VERSION 5.7 ;
  NOWIREEXTENSIONATPIN ON ;
  DIVIDERCHAR "/" ;
  BUSBITCHARS "[]" ;
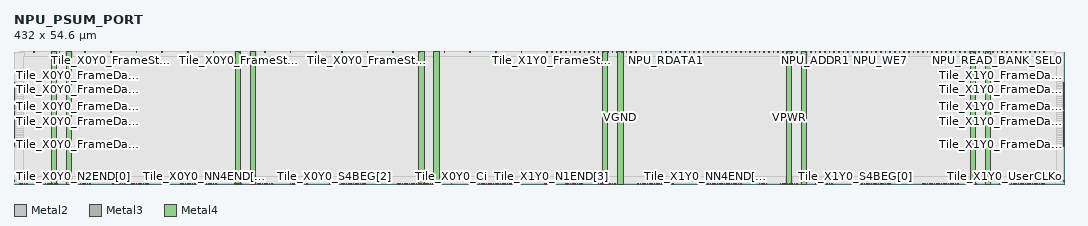
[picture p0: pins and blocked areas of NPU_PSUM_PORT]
MACRO NPU_PSUM_PORT
  CLASS BLOCK ;
  FOREIGN NPU_PSUM_PORT ;
  ORIGIN 0.000 0.000 ;
  SIZE 432.000 BY 54.600 ;
  PIN NPU_ADDR0
    DIRECTION OUTPUT ;
    USE SIGNAL ;
    ANTENNADIFFAREA 2.724000 ;
    PORT
      LAYER Metal2 ;
        RECT 327.640 54.200 328.040 54.600 ;
    END
  END NPU_ADDR0
  PIN NPU_ADDR1
    DIRECTION OUTPUT ;
    USE SIGNAL ;
    ANTENNADIFFAREA 2.724000 ;
    PORT
      LAYER Metal2 ;
        RECT 329.560 54.200 329.960 54.600 ;
    END
  END NPU_ADDR1
  PIN NPU_ADDR2
    DIRECTION OUTPUT ;
    USE SIGNAL ;
    ANTENNADIFFAREA 2.724000 ;
    PORT
      LAYER Metal2 ;
        RECT 331.480 54.200 331.880 54.600 ;
    END
  END NPU_ADDR2
  PIN NPU_ADDR3
    DIRECTION OUTPUT ;
    USE SIGNAL ;
    ANTENNADIFFAREA 2.724000 ;
    PORT
      LAYER Metal2 ;
        RECT 333.400 54.200 333.800 54.600 ;
    END
  END NPU_ADDR3
  PIN NPU_ADDR4
    DIRECTION OUTPUT ;
    USE SIGNAL ;
    ANTENNADIFFAREA 2.724000 ;
    PORT
      LAYER Metal2 ;
        RECT 335.320 54.200 335.720 54.600 ;
    END
  END NPU_ADDR4
  PIN NPU_ADDR5
    DIRECTION OUTPUT ;
    USE SIGNAL ;
    ANTENNADIFFAREA 2.724000 ;
    PORT
      LAYER Metal2 ;
        RECT 337.240 54.200 337.640 54.600 ;
    END
  END NPU_ADDR5
  PIN NPU_ADDR6
    DIRECTION OUTPUT ;
    USE SIGNAL ;
    ANTENNADIFFAREA 2.724000 ;
    PORT
      LAYER Metal2 ;
        RECT 339.160 54.200 339.560 54.600 ;
    END
  END NPU_ADDR6
  PIN NPU_ADDR7
    DIRECTION OUTPUT ;
    USE SIGNAL ;
    ANTENNADIFFAREA 2.724000 ;
    PORT
      LAYER Metal2 ;
        RECT 341.080 54.200 341.480 54.600 ;
    END
  END NPU_ADDR7
  PIN NPU_RDATA0
    DIRECTION INPUT ;
    USE SIGNAL ;
    ANTENNAGATEAREA 0.180700 ;
    ANTENNADIFFAREA 2.015400 ;
    PORT
      LAYER Metal2 ;
        RECT 266.200 54.200 266.600 54.600 ;
    END
  END NPU_RDATA0
  PIN NPU_RDATA1
    DIRECTION INPUT ;
    USE SIGNAL ;
    ANTENNAGATEAREA 0.180700 ;
    ANTENNADIFFAREA 2.015400 ;
    PORT
      LAYER Metal2 ;
        RECT 268.120 54.200 268.520 54.600 ;
    END
  END NPU_RDATA1
  PIN NPU_RDATA10
    DIRECTION INPUT ;
    USE SIGNAL ;
    ANTENNAGATEAREA 0.180700 ;
    ANTENNADIFFAREA 2.015400 ;
    PORT
      LAYER Metal2 ;
        RECT 285.400 54.200 285.800 54.600 ;
    END
  END NPU_RDATA10
  PIN NPU_RDATA11
    DIRECTION INPUT ;
    USE SIGNAL ;
    ANTENNAGATEAREA 0.180700 ;
    ANTENNADIFFAREA 2.015400 ;
    PORT
      LAYER Metal2 ;
        RECT 287.320 54.200 287.720 54.600 ;
    END
  END NPU_RDATA11
  PIN NPU_RDATA12
    DIRECTION INPUT ;
    USE SIGNAL ;
    ANTENNAGATEAREA 0.180700 ;
    ANTENNADIFFAREA 2.015400 ;
    PORT
      LAYER Metal2 ;
        RECT 289.240 54.200 289.640 54.600 ;
    END
  END NPU_RDATA12
  PIN NPU_RDATA13
    DIRECTION INPUT ;
    USE SIGNAL ;
    ANTENNAGATEAREA 0.180700 ;
    ANTENNADIFFAREA 2.015400 ;
    PORT
      LAYER Metal2 ;
        RECT 291.160 54.200 291.560 54.600 ;
    END
  END NPU_RDATA13
  PIN NPU_RDATA14
    DIRECTION INPUT ;
    USE SIGNAL ;
    ANTENNAGATEAREA 0.180700 ;
    ANTENNADIFFAREA 2.015400 ;
    PORT
      LAYER Metal2 ;
        RECT 293.080 54.200 293.480 54.600 ;
    END
  END NPU_RDATA14
  PIN NPU_RDATA15
    DIRECTION INPUT ;
    USE SIGNAL ;
    ANTENNAGATEAREA 0.180700 ;
    ANTENNADIFFAREA 2.015400 ;
    PORT
      LAYER Metal2 ;
        RECT 295.000 54.200 295.400 54.600 ;
    END
  END NPU_RDATA15
  PIN NPU_RDATA16
    DIRECTION INPUT ;
    USE SIGNAL ;
    ANTENNAGATEAREA 0.180700 ;
    ANTENNADIFFAREA 2.015400 ;
    PORT
      LAYER Metal2 ;
        RECT 296.920 54.200 297.320 54.600 ;
    END
  END NPU_RDATA16
  PIN NPU_RDATA17
    DIRECTION INPUT ;
    USE SIGNAL ;
    ANTENNAGATEAREA 0.180700 ;
    ANTENNADIFFAREA 2.015400 ;
    PORT
      LAYER Metal2 ;
        RECT 298.840 54.200 299.240 54.600 ;
    END
  END NPU_RDATA17
  PIN NPU_RDATA18
    DIRECTION INPUT ;
    USE SIGNAL ;
    ANTENNAGATEAREA 0.180700 ;
    ANTENNADIFFAREA 2.015400 ;
    PORT
      LAYER Metal2 ;
        RECT 300.760 54.200 301.160 54.600 ;
    END
  END NPU_RDATA18
  PIN NPU_RDATA19
    DIRECTION INPUT ;
    USE SIGNAL ;
    ANTENNAGATEAREA 0.180700 ;
    ANTENNADIFFAREA 2.015400 ;
    PORT
      LAYER Metal2 ;
        RECT 302.680 54.200 303.080 54.600 ;
    END
  END NPU_RDATA19
  PIN NPU_RDATA2
    DIRECTION INPUT ;
    USE SIGNAL ;
    ANTENNAGATEAREA 0.180700 ;
    ANTENNADIFFAREA 2.015400 ;
    PORT
      LAYER Metal2 ;
        RECT 270.040 54.200 270.440 54.600 ;
    END
  END NPU_RDATA2
  PIN NPU_RDATA20
    DIRECTION INPUT ;
    USE SIGNAL ;
    ANTENNAGATEAREA 0.180700 ;
    ANTENNADIFFAREA 2.015400 ;
    PORT
      LAYER Metal2 ;
        RECT 304.600 54.200 305.000 54.600 ;
    END
  END NPU_RDATA20
  PIN NPU_RDATA21
    DIRECTION INPUT ;
    USE SIGNAL ;
    ANTENNAGATEAREA 0.180700 ;
    ANTENNADIFFAREA 2.015400 ;
    PORT
      LAYER Metal2 ;
        RECT 306.520 54.200 306.920 54.600 ;
    END
  END NPU_RDATA21
  PIN NPU_RDATA22
    DIRECTION INPUT ;
    USE SIGNAL ;
    ANTENNAGATEAREA 0.180700 ;
    ANTENNADIFFAREA 2.015400 ;
    PORT
      LAYER Metal2 ;
        RECT 308.440 54.200 308.840 54.600 ;
    END
  END NPU_RDATA22
  PIN NPU_RDATA23
    DIRECTION INPUT ;
    USE SIGNAL ;
    ANTENNAGATEAREA 0.180700 ;
    ANTENNADIFFAREA 2.015400 ;
    PORT
      LAYER Metal2 ;
        RECT 310.360 54.200 310.760 54.600 ;
    END
  END NPU_RDATA23
  PIN NPU_RDATA24
    DIRECTION INPUT ;
    USE SIGNAL ;
    ANTENNAGATEAREA 0.180700 ;
    ANTENNADIFFAREA 2.015400 ;
    PORT
      LAYER Metal2 ;
        RECT 312.280 54.200 312.680 54.600 ;
    END
  END NPU_RDATA24
  PIN NPU_RDATA25
    DIRECTION INPUT ;
    USE SIGNAL ;
    ANTENNAGATEAREA 0.180700 ;
    ANTENNADIFFAREA 2.015400 ;
    PORT
      LAYER Metal2 ;
        RECT 314.200 54.200 314.600 54.600 ;
    END
  END NPU_RDATA25
  PIN NPU_RDATA26
    DIRECTION INPUT ;
    USE SIGNAL ;
    ANTENNAGATEAREA 0.180700 ;
    ANTENNADIFFAREA 2.015400 ;
    PORT
      LAYER Metal2 ;
        RECT 316.120 54.200 316.520 54.600 ;
    END
  END NPU_RDATA26
  PIN NPU_RDATA27
    DIRECTION INPUT ;
    USE SIGNAL ;
    ANTENNAGATEAREA 0.180700 ;
    ANTENNADIFFAREA 2.015400 ;
    PORT
      LAYER Metal2 ;
        RECT 318.040 54.200 318.440 54.600 ;
    END
  END NPU_RDATA27
  PIN NPU_RDATA28
    DIRECTION INPUT ;
    USE SIGNAL ;
    ANTENNAGATEAREA 0.180700 ;
    ANTENNADIFFAREA 2.015400 ;
    PORT
      LAYER Metal2 ;
        RECT 319.960 54.200 320.360 54.600 ;
    END
  END NPU_RDATA28
  PIN NPU_RDATA29
    DIRECTION INPUT ;
    USE SIGNAL ;
    ANTENNAGATEAREA 0.180700 ;
    ANTENNADIFFAREA 2.015400 ;
    PORT
      LAYER Metal2 ;
        RECT 321.880 54.200 322.280 54.600 ;
    END
  END NPU_RDATA29
  PIN NPU_RDATA3
    DIRECTION INPUT ;
    USE SIGNAL ;
    ANTENNAGATEAREA 0.180700 ;
    ANTENNADIFFAREA 2.015400 ;
    PORT
      LAYER Metal2 ;
        RECT 271.960 54.200 272.360 54.600 ;
    END
  END NPU_RDATA3
  PIN NPU_RDATA30
    DIRECTION INPUT ;
    USE SIGNAL ;
    ANTENNAGATEAREA 0.180700 ;
    ANTENNADIFFAREA 2.015400 ;
    PORT
      LAYER Metal2 ;
        RECT 323.800 54.200 324.200 54.600 ;
    END
  END NPU_RDATA30
  PIN NPU_RDATA31
    DIRECTION INPUT ;
    USE SIGNAL ;
    ANTENNAGATEAREA 0.180700 ;
    ANTENNADIFFAREA 2.015400 ;
    PORT
      LAYER Metal2 ;
        RECT 325.720 54.200 326.120 54.600 ;
    END
  END NPU_RDATA31
  PIN NPU_RDATA4
    DIRECTION INPUT ;
    USE SIGNAL ;
    ANTENNAGATEAREA 0.180700 ;
    ANTENNADIFFAREA 2.015400 ;
    PORT
      LAYER Metal2 ;
        RECT 273.880 54.200 274.280 54.600 ;
    END
  END NPU_RDATA4
  PIN NPU_RDATA5
    DIRECTION INPUT ;
    USE SIGNAL ;
    ANTENNAGATEAREA 0.180700 ;
    ANTENNADIFFAREA 2.015400 ;
    PORT
      LAYER Metal2 ;
        RECT 275.800 54.200 276.200 54.600 ;
    END
  END NPU_RDATA5
  PIN NPU_RDATA6
    DIRECTION INPUT ;
    USE SIGNAL ;
    ANTENNAGATEAREA 0.180700 ;
    ANTENNADIFFAREA 2.015400 ;
    PORT
      LAYER Metal2 ;
        RECT 277.720 54.200 278.120 54.600 ;
    END
  END NPU_RDATA6
  PIN NPU_RDATA7
    DIRECTION INPUT ;
    USE SIGNAL ;
    ANTENNAGATEAREA 0.180700 ;
    ANTENNADIFFAREA 2.015400 ;
    PORT
      LAYER Metal2 ;
        RECT 279.640 54.200 280.040 54.600 ;
    END
  END NPU_RDATA7
  PIN NPU_RDATA8
    DIRECTION INPUT ;
    USE SIGNAL ;
    ANTENNAGATEAREA 0.180700 ;
    ANTENNADIFFAREA 2.015400 ;
    PORT
      LAYER Metal2 ;
        RECT 281.560 54.200 281.960 54.600 ;
    END
  END NPU_RDATA8
  PIN NPU_RDATA9
    DIRECTION INPUT ;
    USE SIGNAL ;
    ANTENNAGATEAREA 0.180700 ;
    ANTENNADIFFAREA 2.015400 ;
    PORT
      LAYER Metal2 ;
        RECT 283.480 54.200 283.880 54.600 ;
    END
  END NPU_RDATA9
  PIN NPU_READ_BANK_SEL0
    DIRECTION OUTPUT ;
    USE SIGNAL ;
    ANTENNADIFFAREA 2.724000 ;
    PORT
      LAYER Metal2 ;
        RECT 419.800 54.200 420.200 54.600 ;
    END
  END NPU_READ_BANK_SEL0
  PIN NPU_READ_BANK_SEL1
    DIRECTION OUTPUT ;
    USE SIGNAL ;
    ANTENNADIFFAREA 2.724000 ;
    PORT
      LAYER Metal2 ;
        RECT 421.720 54.200 422.120 54.600 ;
    END
  END NPU_READ_BANK_SEL1
  PIN NPU_READ_BANK_SEL2
    DIRECTION OUTPUT ;
    USE SIGNAL ;
    ANTENNADIFFAREA 2.724000 ;
    PORT
      LAYER Metal2 ;
        RECT 423.640 54.200 424.040 54.600 ;
    END
  END NPU_READ_BANK_SEL2
  PIN NPU_WDATA0
    DIRECTION OUTPUT ;
    USE SIGNAL ;
    ANTENNADIFFAREA 2.724000 ;
    PORT
      LAYER Metal2 ;
        RECT 358.360 54.200 358.760 54.600 ;
    END
  END NPU_WDATA0
  PIN NPU_WDATA1
    DIRECTION OUTPUT ;
    USE SIGNAL ;
    ANTENNADIFFAREA 2.724000 ;
    PORT
      LAYER Metal2 ;
        RECT 360.280 54.200 360.680 54.600 ;
    END
  END NPU_WDATA1
  PIN NPU_WDATA10
    DIRECTION OUTPUT ;
    USE SIGNAL ;
    ANTENNADIFFAREA 2.724000 ;
    PORT
      LAYER Metal2 ;
        RECT 377.560 54.200 377.960 54.600 ;
    END
  END NPU_WDATA10
  PIN NPU_WDATA11
    DIRECTION OUTPUT ;
    USE SIGNAL ;
    ANTENNADIFFAREA 2.724000 ;
    PORT
      LAYER Metal2 ;
        RECT 379.480 54.200 379.880 54.600 ;
    END
  END NPU_WDATA11
  PIN NPU_WDATA12
    DIRECTION OUTPUT ;
    USE SIGNAL ;
    ANTENNADIFFAREA 2.724000 ;
    PORT
      LAYER Metal2 ;
        RECT 381.400 54.200 381.800 54.600 ;
    END
  END NPU_WDATA12
  PIN NPU_WDATA13
    DIRECTION OUTPUT ;
    USE SIGNAL ;
    ANTENNADIFFAREA 2.724000 ;
    PORT
      LAYER Metal2 ;
        RECT 383.320 54.200 383.720 54.600 ;
    END
  END NPU_WDATA13
  PIN NPU_WDATA14
    DIRECTION OUTPUT ;
    USE SIGNAL ;
    ANTENNADIFFAREA 2.724000 ;
    PORT
      LAYER Metal2 ;
        RECT 385.240 54.200 385.640 54.600 ;
    END
  END NPU_WDATA14
  PIN NPU_WDATA15
    DIRECTION OUTPUT ;
    USE SIGNAL ;
    ANTENNADIFFAREA 2.724000 ;
    PORT
      LAYER Metal2 ;
        RECT 387.160 54.200 387.560 54.600 ;
    END
  END NPU_WDATA15
  PIN NPU_WDATA16
    DIRECTION OUTPUT ;
    USE SIGNAL ;
    ANTENNADIFFAREA 2.724000 ;
    PORT
      LAYER Metal2 ;
        RECT 389.080 54.200 389.480 54.600 ;
    END
  END NPU_WDATA16
  PIN NPU_WDATA17
    DIRECTION OUTPUT ;
    USE SIGNAL ;
    ANTENNADIFFAREA 2.724000 ;
    PORT
      LAYER Metal2 ;
        RECT 391.000 54.200 391.400 54.600 ;
    END
  END NPU_WDATA17
  PIN NPU_WDATA18
    DIRECTION OUTPUT ;
    USE SIGNAL ;
    ANTENNADIFFAREA 2.724000 ;
    PORT
      LAYER Metal2 ;
        RECT 392.920 54.200 393.320 54.600 ;
    END
  END NPU_WDATA18
  PIN NPU_WDATA19
    DIRECTION OUTPUT ;
    USE SIGNAL ;
    ANTENNADIFFAREA 2.724000 ;
    PORT
      LAYER Metal2 ;
        RECT 394.840 54.200 395.240 54.600 ;
    END
  END NPU_WDATA19
  PIN NPU_WDATA2
    DIRECTION OUTPUT ;
    USE SIGNAL ;
    ANTENNADIFFAREA 2.724000 ;
    PORT
      LAYER Metal2 ;
        RECT 362.200 54.200 362.600 54.600 ;
    END
  END NPU_WDATA2
  PIN NPU_WDATA20
    DIRECTION OUTPUT ;
    USE SIGNAL ;
    ANTENNADIFFAREA 2.724000 ;
    PORT
      LAYER Metal2 ;
        RECT 396.760 54.200 397.160 54.600 ;
    END
  END NPU_WDATA20
  PIN NPU_WDATA21
    DIRECTION OUTPUT ;
    USE SIGNAL ;
    ANTENNADIFFAREA 2.724000 ;
    PORT
      LAYER Metal2 ;
        RECT 398.680 54.200 399.080 54.600 ;
    END
  END NPU_WDATA21
  PIN NPU_WDATA22
    DIRECTION OUTPUT ;
    USE SIGNAL ;
    ANTENNADIFFAREA 2.724000 ;
    PORT
      LAYER Metal2 ;
        RECT 400.600 54.200 401.000 54.600 ;
    END
  END NPU_WDATA22
  PIN NPU_WDATA23
    DIRECTION OUTPUT ;
    USE SIGNAL ;
    ANTENNADIFFAREA 2.724000 ;
    PORT
      LAYER Metal2 ;
        RECT 402.520 54.200 402.920 54.600 ;
    END
  END NPU_WDATA23
  PIN NPU_WDATA24
    DIRECTION OUTPUT ;
    USE SIGNAL ;
    ANTENNADIFFAREA 2.724000 ;
    PORT
      LAYER Metal2 ;
        RECT 404.440 54.200 404.840 54.600 ;
    END
  END NPU_WDATA24
  PIN NPU_WDATA25
    DIRECTION OUTPUT ;
    USE SIGNAL ;
    ANTENNADIFFAREA 2.724000 ;
    PORT
      LAYER Metal2 ;
        RECT 406.360 54.200 406.760 54.600 ;
    END
  END NPU_WDATA25
  PIN NPU_WDATA26
    DIRECTION OUTPUT ;
    USE SIGNAL ;
    ANTENNADIFFAREA 2.724000 ;
    PORT
      LAYER Metal2 ;
        RECT 408.280 54.200 408.680 54.600 ;
    END
  END NPU_WDATA26
  PIN NPU_WDATA27
    DIRECTION OUTPUT ;
    USE SIGNAL ;
    ANTENNADIFFAREA 2.724000 ;
    PORT
      LAYER Metal2 ;
        RECT 410.200 54.200 410.600 54.600 ;
    END
  END NPU_WDATA27
  PIN NPU_WDATA28
    DIRECTION OUTPUT ;
    USE SIGNAL ;
    ANTENNADIFFAREA 2.724000 ;
    PORT
      LAYER Metal2 ;
        RECT 412.120 54.200 412.520 54.600 ;
    END
  END NPU_WDATA28
  PIN NPU_WDATA29
    DIRECTION OUTPUT ;
    USE SIGNAL ;
    ANTENNADIFFAREA 2.724000 ;
    PORT
      LAYER Metal2 ;
        RECT 414.040 54.200 414.440 54.600 ;
    END
  END NPU_WDATA29
  PIN NPU_WDATA3
    DIRECTION OUTPUT ;
    USE SIGNAL ;
    ANTENNADIFFAREA 2.724000 ;
    PORT
      LAYER Metal2 ;
        RECT 364.120 54.200 364.520 54.600 ;
    END
  END NPU_WDATA3
  PIN NPU_WDATA30
    DIRECTION OUTPUT ;
    USE SIGNAL ;
    ANTENNADIFFAREA 2.724000 ;
    PORT
      LAYER Metal2 ;
        RECT 415.960 54.200 416.360 54.600 ;
    END
  END NPU_WDATA30
  PIN NPU_WDATA31
    DIRECTION OUTPUT ;
    USE SIGNAL ;
    ANTENNADIFFAREA 2.724000 ;
    PORT
      LAYER Metal2 ;
        RECT 417.880 54.200 418.280 54.600 ;
    END
  END NPU_WDATA31
  PIN NPU_WDATA4
    DIRECTION OUTPUT ;
    USE SIGNAL ;
    ANTENNADIFFAREA 2.724000 ;
    PORT
      LAYER Metal2 ;
        RECT 366.040 54.200 366.440 54.600 ;
    END
  END NPU_WDATA4
  PIN NPU_WDATA5
    DIRECTION OUTPUT ;
    USE SIGNAL ;
    ANTENNADIFFAREA 2.724000 ;
    PORT
      LAYER Metal2 ;
        RECT 367.960 54.200 368.360 54.600 ;
    END
  END NPU_WDATA5
  PIN NPU_WDATA6
    DIRECTION OUTPUT ;
    USE SIGNAL ;
    ANTENNADIFFAREA 2.724000 ;
    PORT
      LAYER Metal2 ;
        RECT 369.880 54.200 370.280 54.600 ;
    END
  END NPU_WDATA6
  PIN NPU_WDATA7
    DIRECTION OUTPUT ;
    USE SIGNAL ;
    ANTENNADIFFAREA 2.724000 ;
    PORT
      LAYER Metal2 ;
        RECT 371.800 54.200 372.200 54.600 ;
    END
  END NPU_WDATA7
  PIN NPU_WDATA8
    DIRECTION OUTPUT ;
    USE SIGNAL ;
    ANTENNADIFFAREA 2.724000 ;
    PORT
      LAYER Metal2 ;
        RECT 373.720 54.200 374.120 54.600 ;
    END
  END NPU_WDATA8
  PIN NPU_WDATA9
    DIRECTION OUTPUT ;
    USE SIGNAL ;
    ANTENNADIFFAREA 2.724000 ;
    PORT
      LAYER Metal2 ;
        RECT 375.640 54.200 376.040 54.600 ;
    END
  END NPU_WDATA9
  PIN NPU_WE0
    DIRECTION OUTPUT ;
    USE SIGNAL ;
    ANTENNADIFFAREA 2.724000 ;
    PORT
      LAYER Metal2 ;
        RECT 343.000 54.200 343.400 54.600 ;
    END
  END NPU_WE0
  PIN NPU_WE1
    DIRECTION OUTPUT ;
    USE SIGNAL ;
    ANTENNADIFFAREA 2.724000 ;
    PORT
      LAYER Metal2 ;
        RECT 344.920 54.200 345.320 54.600 ;
    END
  END NPU_WE1
  PIN NPU_WE2
    DIRECTION OUTPUT ;
    USE SIGNAL ;
    ANTENNADIFFAREA 2.724000 ;
    PORT
      LAYER Metal2 ;
        RECT 346.840 54.200 347.240 54.600 ;
    END
  END NPU_WE2
  PIN NPU_WE3
    DIRECTION OUTPUT ;
    USE SIGNAL ;
    ANTENNADIFFAREA 2.724000 ;
    PORT
      LAYER Metal2 ;
        RECT 348.760 54.200 349.160 54.600 ;
    END
  END NPU_WE3
  PIN NPU_WE4
    DIRECTION OUTPUT ;
    USE SIGNAL ;
    ANTENNADIFFAREA 2.724000 ;
    PORT
      LAYER Metal2 ;
        RECT 350.680 54.200 351.080 54.600 ;
    END
  END NPU_WE4
  PIN NPU_WE5
    DIRECTION OUTPUT ;
    USE SIGNAL ;
    ANTENNADIFFAREA 2.724000 ;
    PORT
      LAYER Metal2 ;
        RECT 352.600 54.200 353.000 54.600 ;
    END
  END NPU_WE5
  PIN NPU_WE6
    DIRECTION OUTPUT ;
    USE SIGNAL ;
    ANTENNADIFFAREA 2.724000 ;
    PORT
      LAYER Metal2 ;
        RECT 354.520 54.200 354.920 54.600 ;
    END
  END NPU_WE6
  PIN NPU_WE7
    DIRECTION OUTPUT ;
    USE SIGNAL ;
    ANTENNADIFFAREA 2.724000 ;
    PORT
      LAYER Metal2 ;
        RECT 356.440 54.200 356.840 54.600 ;
    END
  END NPU_WE7
  PIN Tile_X0Y0_Ci
    DIRECTION INPUT ;
    USE SIGNAL ;
    PORT
      LAYER Metal2 ;
        RECT 179.800 0.000 180.200 0.400 ;
    END
  END Tile_X0Y0_Ci
  PIN Tile_X0Y0_FrameData[0]
    DIRECTION INPUT ;
    USE SIGNAL ;
    ANTENNAGATEAREA 0.180700 ;
    ANTENNADIFFAREA 2.015400 ;
    PORT
      LAYER Metal3 ;
        RECT 0.000 15.340 0.400 15.740 ;
    END
  END Tile_X0Y0_FrameData[0]
  PIN Tile_X0Y0_FrameData[10]
    DIRECTION INPUT ;
    USE SIGNAL ;
    ANTENNAGATEAREA 0.180700 ;
    ANTENNADIFFAREA 2.015400 ;
    PORT
      LAYER Metal3 ;
        RECT 0.000 23.740 0.400 24.140 ;
    END
  END Tile_X0Y0_FrameData[10]
  PIN Tile_X0Y0_FrameData[11]
    DIRECTION INPUT ;
    USE SIGNAL ;
    ANTENNAGATEAREA 0.180700 ;
    ANTENNADIFFAREA 2.015400 ;
    PORT
      LAYER Metal3 ;
        RECT 0.000 24.580 0.400 24.980 ;
    END
  END Tile_X0Y0_FrameData[11]
  PIN Tile_X0Y0_FrameData[12]
    DIRECTION INPUT ;
    USE SIGNAL ;
    ANTENNAGATEAREA 0.180700 ;
    ANTENNADIFFAREA 2.015400 ;
    PORT
      LAYER Metal3 ;
        RECT 0.000 25.420 0.400 25.820 ;
    END
  END Tile_X0Y0_FrameData[12]
  PIN Tile_X0Y0_FrameData[13]
    DIRECTION INPUT ;
    USE SIGNAL ;
    ANTENNAGATEAREA 0.180700 ;
    ANTENNADIFFAREA 2.015400 ;
    PORT
      LAYER Metal3 ;
        RECT 0.000 26.260 0.400 26.660 ;
    END
  END Tile_X0Y0_FrameData[13]
  PIN Tile_X0Y0_FrameData[14]
    DIRECTION INPUT ;
    USE SIGNAL ;
    ANTENNAGATEAREA 0.180700 ;
    ANTENNADIFFAREA 2.015400 ;
    PORT
      LAYER Metal3 ;
        RECT 0.000 27.100 0.400 27.500 ;
    END
  END Tile_X0Y0_FrameData[14]
  PIN Tile_X0Y0_FrameData[15]
    DIRECTION INPUT ;
    USE SIGNAL ;
    ANTENNAGATEAREA 0.180700 ;
    ANTENNADIFFAREA 2.015400 ;
    PORT
      LAYER Metal3 ;
        RECT 0.000 27.940 0.400 28.340 ;
    END
  END Tile_X0Y0_FrameData[15]
  PIN Tile_X0Y0_FrameData[16]
    DIRECTION INPUT ;
    USE SIGNAL ;
    ANTENNAGATEAREA 0.180700 ;
    ANTENNADIFFAREA 2.015400 ;
    PORT
      LAYER Metal3 ;
        RECT 0.000 28.780 0.400 29.180 ;
    END
  END Tile_X0Y0_FrameData[16]
  PIN Tile_X0Y0_FrameData[17]
    DIRECTION INPUT ;
    USE SIGNAL ;
    ANTENNAGATEAREA 0.180700 ;
    ANTENNADIFFAREA 2.015400 ;
    PORT
      LAYER Metal3 ;
        RECT 0.000 29.620 0.400 30.020 ;
    END
  END Tile_X0Y0_FrameData[17]
  PIN Tile_X0Y0_FrameData[18]
    DIRECTION INPUT ;
    USE SIGNAL ;
    ANTENNAGATEAREA 0.180700 ;
    ANTENNADIFFAREA 2.015400 ;
    PORT
      LAYER Metal3 ;
        RECT 0.000 30.460 0.400 30.860 ;
    END
  END Tile_X0Y0_FrameData[18]
  PIN Tile_X0Y0_FrameData[19]
    DIRECTION INPUT ;
    USE SIGNAL ;
    ANTENNAGATEAREA 0.180700 ;
    ANTENNADIFFAREA 2.015400 ;
    PORT
      LAYER Metal3 ;
        RECT 0.000 31.300 0.400 31.700 ;
    END
  END Tile_X0Y0_FrameData[19]
  PIN Tile_X0Y0_FrameData[1]
    DIRECTION INPUT ;
    USE SIGNAL ;
    ANTENNAGATEAREA 0.180700 ;
    ANTENNADIFFAREA 2.015400 ;
    PORT
      LAYER Metal3 ;
        RECT 0.000 16.180 0.400 16.580 ;
    END
  END Tile_X0Y0_FrameData[1]
  PIN Tile_X0Y0_FrameData[20]
    DIRECTION INPUT ;
    USE SIGNAL ;
    ANTENNAGATEAREA 0.180700 ;
    ANTENNADIFFAREA 2.015400 ;
    PORT
      LAYER Metal3 ;
        RECT 0.000 32.140 0.400 32.540 ;
    END
  END Tile_X0Y0_FrameData[20]
  PIN Tile_X0Y0_FrameData[21]
    DIRECTION INPUT ;
    USE SIGNAL ;
    ANTENNAGATEAREA 0.180700 ;
    ANTENNADIFFAREA 2.015400 ;
    PORT
      LAYER Metal3 ;
        RECT 0.000 32.980 0.400 33.380 ;
    END
  END Tile_X0Y0_FrameData[21]
  PIN Tile_X0Y0_FrameData[22]
    DIRECTION INPUT ;
    USE SIGNAL ;
    ANTENNAGATEAREA 0.180700 ;
    ANTENNADIFFAREA 2.015400 ;
    PORT
      LAYER Metal3 ;
        RECT 0.000 33.820 0.400 34.220 ;
    END
  END Tile_X0Y0_FrameData[22]
  PIN Tile_X0Y0_FrameData[23]
    DIRECTION INPUT ;
    USE SIGNAL ;
    ANTENNAGATEAREA 0.180700 ;
    ANTENNADIFFAREA 2.015400 ;
    PORT
      LAYER Metal3 ;
        RECT 0.000 34.660 0.400 35.060 ;
    END
  END Tile_X0Y0_FrameData[23]
  PIN Tile_X0Y0_FrameData[24]
    DIRECTION INPUT ;
    USE SIGNAL ;
    ANTENNAGATEAREA 0.180700 ;
    ANTENNADIFFAREA 2.015400 ;
    PORT
      LAYER Metal3 ;
        RECT 0.000 35.500 0.400 35.900 ;
    END
  END Tile_X0Y0_FrameData[24]
  PIN Tile_X0Y0_FrameData[25]
    DIRECTION INPUT ;
    USE SIGNAL ;
    ANTENNAGATEAREA 0.180700 ;
    ANTENNADIFFAREA 2.015400 ;
    PORT
      LAYER Metal3 ;
        RECT 0.000 36.340 0.400 36.740 ;
    END
  END Tile_X0Y0_FrameData[25]
  PIN Tile_X0Y0_FrameData[26]
    DIRECTION INPUT ;
    USE SIGNAL ;
    ANTENNAGATEAREA 0.180700 ;
    ANTENNADIFFAREA 2.015400 ;
    PORT
      LAYER Metal3 ;
        RECT 0.000 37.180 0.400 37.580 ;
    END
  END Tile_X0Y0_FrameData[26]
  PIN Tile_X0Y0_FrameData[27]
    DIRECTION INPUT ;
    USE SIGNAL ;
    ANTENNAGATEAREA 0.180700 ;
    ANTENNADIFFAREA 2.015400 ;
    PORT
      LAYER Metal3 ;
        RECT 0.000 38.020 0.400 38.420 ;
    END
  END Tile_X0Y0_FrameData[27]
  PIN Tile_X0Y0_FrameData[28]
    DIRECTION INPUT ;
    USE SIGNAL ;
    ANTENNAGATEAREA 0.180700 ;
    ANTENNADIFFAREA 2.015400 ;
    PORT
      LAYER Metal3 ;
        RECT 0.000 38.860 0.400 39.260 ;
    END
  END Tile_X0Y0_FrameData[28]
  PIN Tile_X0Y0_FrameData[29]
    DIRECTION INPUT ;
    USE SIGNAL ;
    ANTENNAGATEAREA 0.180700 ;
    ANTENNADIFFAREA 2.015400 ;
    PORT
      LAYER Metal3 ;
        RECT 0.000 39.700 0.400 40.100 ;
    END
  END Tile_X0Y0_FrameData[29]
  PIN Tile_X0Y0_FrameData[2]
    DIRECTION INPUT ;
    USE SIGNAL ;
    ANTENNAGATEAREA 0.180700 ;
    ANTENNADIFFAREA 2.015400 ;
    PORT
      LAYER Metal3 ;
        RECT 0.000 17.020 0.400 17.420 ;
    END
  END Tile_X0Y0_FrameData[2]
  PIN Tile_X0Y0_FrameData[30]
    DIRECTION INPUT ;
    USE SIGNAL ;
    ANTENNAGATEAREA 0.180700 ;
    ANTENNADIFFAREA 2.015400 ;
    PORT
      LAYER Metal3 ;
        RECT 0.000 40.540 0.400 40.940 ;
    END
  END Tile_X0Y0_FrameData[30]
  PIN Tile_X0Y0_FrameData[31]
    DIRECTION INPUT ;
    USE SIGNAL ;
    ANTENNAGATEAREA 0.180700 ;
    ANTENNADIFFAREA 2.015400 ;
    PORT
      LAYER Metal3 ;
        RECT 0.000 41.380 0.400 41.780 ;
    END
  END Tile_X0Y0_FrameData[31]
  PIN Tile_X0Y0_FrameData[3]
    DIRECTION INPUT ;
    USE SIGNAL ;
    ANTENNAGATEAREA 0.180700 ;
    ANTENNADIFFAREA 2.015400 ;
    PORT
      LAYER Metal3 ;
        RECT 0.000 17.860 0.400 18.260 ;
    END
  END Tile_X0Y0_FrameData[3]
  PIN Tile_X0Y0_FrameData[4]
    DIRECTION INPUT ;
    USE SIGNAL ;
    ANTENNAGATEAREA 0.180700 ;
    ANTENNADIFFAREA 2.015400 ;
    PORT
      LAYER Metal3 ;
        RECT 0.000 18.700 0.400 19.100 ;
    END
  END Tile_X0Y0_FrameData[4]
  PIN Tile_X0Y0_FrameData[5]
    DIRECTION INPUT ;
    USE SIGNAL ;
    ANTENNAGATEAREA 0.180700 ;
    ANTENNADIFFAREA 2.015400 ;
    PORT
      LAYER Metal3 ;
        RECT 0.000 19.540 0.400 19.940 ;
    END
  END Tile_X0Y0_FrameData[5]
  PIN Tile_X0Y0_FrameData[6]
    DIRECTION INPUT ;
    USE SIGNAL ;
    ANTENNAGATEAREA 0.180700 ;
    ANTENNADIFFAREA 2.015400 ;
    PORT
      LAYER Metal3 ;
        RECT 0.000 20.380 0.400 20.780 ;
    END
  END Tile_X0Y0_FrameData[6]
  PIN Tile_X0Y0_FrameData[7]
    DIRECTION INPUT ;
    USE SIGNAL ;
    ANTENNAGATEAREA 0.180700 ;
    ANTENNADIFFAREA 2.015400 ;
    PORT
      LAYER Metal3 ;
        RECT 0.000 21.220 0.400 21.620 ;
    END
  END Tile_X0Y0_FrameData[7]
  PIN Tile_X0Y0_FrameData[8]
    DIRECTION INPUT ;
    USE SIGNAL ;
    ANTENNAGATEAREA 0.180700 ;
    ANTENNADIFFAREA 2.015400 ;
    PORT
      LAYER Metal3 ;
        RECT 0.000 22.060 0.400 22.460 ;
    END
  END Tile_X0Y0_FrameData[8]
  PIN Tile_X0Y0_FrameData[9]
    DIRECTION INPUT ;
    USE SIGNAL ;
    ANTENNAGATEAREA 0.180700 ;
    ANTENNADIFFAREA 2.015400 ;
    PORT
      LAYER Metal3 ;
        RECT 0.000 22.900 0.400 23.300 ;
    END
  END Tile_X0Y0_FrameData[9]
  PIN Tile_X0Y0_FrameStrobe[0]
    DIRECTION INPUT ;
    USE SIGNAL ;
    ANTENNAGATEAREA 0.180700 ;
    ANTENNADIFFAREA 2.015400 ;
    PORT
      LAYER Metal2 ;
        RECT 189.400 0.000 189.800 0.400 ;
    END
  END Tile_X0Y0_FrameStrobe[0]
  PIN Tile_X0Y0_FrameStrobe[10]
    DIRECTION INPUT ;
    USE SIGNAL ;
    ANTENNAGATEAREA 0.180700 ;
    ANTENNADIFFAREA 2.015400 ;
    PORT
      LAYER Metal2 ;
        RECT 199.000 0.000 199.400 0.400 ;
    END
  END Tile_X0Y0_FrameStrobe[10]
  PIN Tile_X0Y0_FrameStrobe[11]
    DIRECTION INPUT ;
    USE SIGNAL ;
    ANTENNAGATEAREA 0.180700 ;
    ANTENNADIFFAREA 2.015400 ;
    PORT
      LAYER Metal2 ;
        RECT 199.960 0.000 200.360 0.400 ;
    END
  END Tile_X0Y0_FrameStrobe[11]
  PIN Tile_X0Y0_FrameStrobe[12]
    DIRECTION INPUT ;
    USE SIGNAL ;
    ANTENNAGATEAREA 0.180700 ;
    ANTENNADIFFAREA 2.015400 ;
    PORT
      LAYER Metal2 ;
        RECT 200.920 0.000 201.320 0.400 ;
    END
  END Tile_X0Y0_FrameStrobe[12]
  PIN Tile_X0Y0_FrameStrobe[13]
    DIRECTION INPUT ;
    USE SIGNAL ;
    ANTENNAGATEAREA 0.180700 ;
    ANTENNADIFFAREA 2.015400 ;
    PORT
      LAYER Metal2 ;
        RECT 201.880 0.000 202.280 0.400 ;
    END
  END Tile_X0Y0_FrameStrobe[13]
  PIN Tile_X0Y0_FrameStrobe[14]
    DIRECTION INPUT ;
    USE SIGNAL ;
    ANTENNAGATEAREA 0.180700 ;
    ANTENNADIFFAREA 2.015400 ;
    PORT
      LAYER Metal2 ;
        RECT 202.840 0.000 203.240 0.400 ;
    END
  END Tile_X0Y0_FrameStrobe[14]
  PIN Tile_X0Y0_FrameStrobe[15]
    DIRECTION INPUT ;
    USE SIGNAL ;
    ANTENNAGATEAREA 0.180700 ;
    ANTENNADIFFAREA 2.015400 ;
    PORT
      LAYER Metal2 ;
        RECT 203.800 0.000 204.200 0.400 ;
    END
  END Tile_X0Y0_FrameStrobe[15]
  PIN Tile_X0Y0_FrameStrobe[16]
    DIRECTION INPUT ;
    USE SIGNAL ;
    ANTENNAGATEAREA 0.180700 ;
    ANTENNADIFFAREA 2.015400 ;
    PORT
      LAYER Metal2 ;
        RECT 204.760 0.000 205.160 0.400 ;
    END
  END Tile_X0Y0_FrameStrobe[16]
  PIN Tile_X0Y0_FrameStrobe[17]
    DIRECTION INPUT ;
    USE SIGNAL ;
    ANTENNAGATEAREA 0.180700 ;
    ANTENNADIFFAREA 2.015400 ;
    PORT
      LAYER Metal2 ;
        RECT 205.720 0.000 206.120 0.400 ;
    END
  END Tile_X0Y0_FrameStrobe[17]
  PIN Tile_X0Y0_FrameStrobe[18]
    DIRECTION INPUT ;
    USE SIGNAL ;
    ANTENNAGATEAREA 0.180700 ;
    ANTENNADIFFAREA 2.015400 ;
    PORT
      LAYER Metal2 ;
        RECT 206.680 0.000 207.080 0.400 ;
    END
  END Tile_X0Y0_FrameStrobe[18]
  PIN Tile_X0Y0_FrameStrobe[19]
    DIRECTION INPUT ;
    USE SIGNAL ;
    ANTENNAGATEAREA 0.180700 ;
    ANTENNADIFFAREA 2.015400 ;
    PORT
      LAYER Metal2 ;
        RECT 207.640 0.000 208.040 0.400 ;
    END
  END Tile_X0Y0_FrameStrobe[19]
  PIN Tile_X0Y0_FrameStrobe[1]
    DIRECTION INPUT ;
    USE SIGNAL ;
    ANTENNAGATEAREA 0.180700 ;
    ANTENNADIFFAREA 2.015400 ;
    PORT
      LAYER Metal2 ;
        RECT 190.360 0.000 190.760 0.400 ;
    END
  END Tile_X0Y0_FrameStrobe[1]
  PIN Tile_X0Y0_FrameStrobe[2]
    DIRECTION INPUT ;
    USE SIGNAL ;
    ANTENNAGATEAREA 0.180700 ;
    ANTENNADIFFAREA 2.015400 ;
    PORT
      LAYER Metal2 ;
        RECT 191.320 0.000 191.720 0.400 ;
    END
  END Tile_X0Y0_FrameStrobe[2]
  PIN Tile_X0Y0_FrameStrobe[3]
    DIRECTION INPUT ;
    USE SIGNAL ;
    ANTENNAGATEAREA 0.180700 ;
    ANTENNADIFFAREA 2.015400 ;
    PORT
      LAYER Metal2 ;
        RECT 192.280 0.000 192.680 0.400 ;
    END
  END Tile_X0Y0_FrameStrobe[3]
  PIN Tile_X0Y0_FrameStrobe[4]
    DIRECTION INPUT ;
    USE SIGNAL ;
    ANTENNAGATEAREA 0.180700 ;
    ANTENNADIFFAREA 2.015400 ;
    PORT
      LAYER Metal2 ;
        RECT 193.240 0.000 193.640 0.400 ;
    END
  END Tile_X0Y0_FrameStrobe[4]
  PIN Tile_X0Y0_FrameStrobe[5]
    DIRECTION INPUT ;
    USE SIGNAL ;
    ANTENNAGATEAREA 0.180700 ;
    ANTENNADIFFAREA 2.015400 ;
    PORT
      LAYER Metal2 ;
        RECT 194.200 0.000 194.600 0.400 ;
    END
  END Tile_X0Y0_FrameStrobe[5]
  PIN Tile_X0Y0_FrameStrobe[6]
    DIRECTION INPUT ;
    USE SIGNAL ;
    ANTENNAGATEAREA 0.180700 ;
    ANTENNADIFFAREA 2.015400 ;
    PORT
      LAYER Metal2 ;
        RECT 195.160 0.000 195.560 0.400 ;
    END
  END Tile_X0Y0_FrameStrobe[6]
  PIN Tile_X0Y0_FrameStrobe[7]
    DIRECTION INPUT ;
    USE SIGNAL ;
    ANTENNAGATEAREA 0.180700 ;
    ANTENNADIFFAREA 2.015400 ;
    PORT
      LAYER Metal2 ;
        RECT 196.120 0.000 196.520 0.400 ;
    END
  END Tile_X0Y0_FrameStrobe[7]
  PIN Tile_X0Y0_FrameStrobe[8]
    DIRECTION INPUT ;
    USE SIGNAL ;
    ANTENNAGATEAREA 0.180700 ;
    ANTENNADIFFAREA 2.015400 ;
    PORT
      LAYER Metal2 ;
        RECT 197.080 0.000 197.480 0.400 ;
    END
  END Tile_X0Y0_FrameStrobe[8]
  PIN Tile_X0Y0_FrameStrobe[9]
    DIRECTION INPUT ;
    USE SIGNAL ;
    ANTENNAGATEAREA 0.180700 ;
    ANTENNADIFFAREA 2.015400 ;
    PORT
      LAYER Metal2 ;
        RECT 198.040 0.000 198.440 0.400 ;
    END
  END Tile_X0Y0_FrameStrobe[9]
  PIN Tile_X0Y0_FrameStrobe_O[0]
    DIRECTION OUTPUT ;
    USE SIGNAL ;
    ANTENNADIFFAREA 2.724000 ;
    PORT
      LAYER Metal2 ;
        RECT 7.960 54.200 8.360 54.600 ;
    END
  END Tile_X0Y0_FrameStrobe_O[0]
  PIN Tile_X0Y0_FrameStrobe_O[10]
    DIRECTION OUTPUT ;
    USE SIGNAL ;
    ANTENNADIFFAREA 2.724000 ;
    PORT
      LAYER Metal2 ;
        RECT 113.560 54.200 113.960 54.600 ;
    END
  END Tile_X0Y0_FrameStrobe_O[10]
  PIN Tile_X0Y0_FrameStrobe_O[11]
    DIRECTION OUTPUT ;
    USE SIGNAL ;
    ANTENNADIFFAREA 2.724000 ;
    PORT
      LAYER Metal2 ;
        RECT 124.120 54.200 124.520 54.600 ;
    END
  END Tile_X0Y0_FrameStrobe_O[11]
  PIN Tile_X0Y0_FrameStrobe_O[12]
    DIRECTION OUTPUT ;
    USE SIGNAL ;
    ANTENNADIFFAREA 2.724000 ;
    PORT
      LAYER Metal2 ;
        RECT 134.680 54.200 135.080 54.600 ;
    END
  END Tile_X0Y0_FrameStrobe_O[12]
  PIN Tile_X0Y0_FrameStrobe_O[13]
    DIRECTION OUTPUT ;
    USE SIGNAL ;
    ANTENNADIFFAREA 2.724000 ;
    PORT
      LAYER Metal2 ;
        RECT 145.240 54.200 145.640 54.600 ;
    END
  END Tile_X0Y0_FrameStrobe_O[13]
  PIN Tile_X0Y0_FrameStrobe_O[14]
    DIRECTION OUTPUT ;
    USE SIGNAL ;
    ANTENNADIFFAREA 2.724000 ;
    PORT
      LAYER Metal2 ;
        RECT 155.800 54.200 156.200 54.600 ;
    END
  END Tile_X0Y0_FrameStrobe_O[14]
  PIN Tile_X0Y0_FrameStrobe_O[15]
    DIRECTION OUTPUT ;
    USE SIGNAL ;
    ANTENNADIFFAREA 2.724000 ;
    PORT
      LAYER Metal2 ;
        RECT 166.360 54.200 166.760 54.600 ;
    END
  END Tile_X0Y0_FrameStrobe_O[15]
  PIN Tile_X0Y0_FrameStrobe_O[16]
    DIRECTION OUTPUT ;
    USE SIGNAL ;
    ANTENNADIFFAREA 2.724000 ;
    PORT
      LAYER Metal2 ;
        RECT 176.920 54.200 177.320 54.600 ;
    END
  END Tile_X0Y0_FrameStrobe_O[16]
  PIN Tile_X0Y0_FrameStrobe_O[17]
    DIRECTION OUTPUT ;
    USE SIGNAL ;
    ANTENNADIFFAREA 2.724000 ;
    PORT
      LAYER Metal2 ;
        RECT 187.480 54.200 187.880 54.600 ;
    END
  END Tile_X0Y0_FrameStrobe_O[17]
  PIN Tile_X0Y0_FrameStrobe_O[18]
    DIRECTION OUTPUT ;
    USE SIGNAL ;
    ANTENNADIFFAREA 2.724000 ;
    PORT
      LAYER Metal2 ;
        RECT 198.040 54.200 198.440 54.600 ;
    END
  END Tile_X0Y0_FrameStrobe_O[18]
  PIN Tile_X0Y0_FrameStrobe_O[19]
    DIRECTION OUTPUT ;
    USE SIGNAL ;
    ANTENNADIFFAREA 2.724000 ;
    PORT
      LAYER Metal2 ;
        RECT 208.600 54.200 209.000 54.600 ;
    END
  END Tile_X0Y0_FrameStrobe_O[19]
  PIN Tile_X0Y0_FrameStrobe_O[1]
    DIRECTION OUTPUT ;
    USE SIGNAL ;
    ANTENNADIFFAREA 2.724000 ;
    PORT
      LAYER Metal2 ;
        RECT 18.520 54.200 18.920 54.600 ;
    END
  END Tile_X0Y0_FrameStrobe_O[1]
  PIN Tile_X0Y0_FrameStrobe_O[2]
    DIRECTION OUTPUT ;
    USE SIGNAL ;
    ANTENNADIFFAREA 2.724000 ;
    PORT
      LAYER Metal2 ;
        RECT 29.080 54.200 29.480 54.600 ;
    END
  END Tile_X0Y0_FrameStrobe_O[2]
  PIN Tile_X0Y0_FrameStrobe_O[3]
    DIRECTION OUTPUT ;
    USE SIGNAL ;
    ANTENNADIFFAREA 2.724000 ;
    PORT
      LAYER Metal2 ;
        RECT 39.640 54.200 40.040 54.600 ;
    END
  END Tile_X0Y0_FrameStrobe_O[3]
  PIN Tile_X0Y0_FrameStrobe_O[4]
    DIRECTION OUTPUT ;
    USE SIGNAL ;
    ANTENNADIFFAREA 2.724000 ;
    PORT
      LAYER Metal2 ;
        RECT 50.200 54.200 50.600 54.600 ;
    END
  END Tile_X0Y0_FrameStrobe_O[4]
  PIN Tile_X0Y0_FrameStrobe_O[5]
    DIRECTION OUTPUT ;
    USE SIGNAL ;
    ANTENNADIFFAREA 2.724000 ;
    PORT
      LAYER Metal2 ;
        RECT 60.760 54.200 61.160 54.600 ;
    END
  END Tile_X0Y0_FrameStrobe_O[5]
  PIN Tile_X0Y0_FrameStrobe_O[6]
    DIRECTION OUTPUT ;
    USE SIGNAL ;
    ANTENNADIFFAREA 2.724000 ;
    PORT
      LAYER Metal2 ;
        RECT 71.320 54.200 71.720 54.600 ;
    END
  END Tile_X0Y0_FrameStrobe_O[6]
  PIN Tile_X0Y0_FrameStrobe_O[7]
    DIRECTION OUTPUT ;
    USE SIGNAL ;
    ANTENNADIFFAREA 2.724000 ;
    PORT
      LAYER Metal2 ;
        RECT 81.880 54.200 82.280 54.600 ;
    END
  END Tile_X0Y0_FrameStrobe_O[7]
  PIN Tile_X0Y0_FrameStrobe_O[8]
    DIRECTION OUTPUT ;
    USE SIGNAL ;
    ANTENNADIFFAREA 2.724000 ;
    PORT
      LAYER Metal2 ;
        RECT 92.440 54.200 92.840 54.600 ;
    END
  END Tile_X0Y0_FrameStrobe_O[8]
  PIN Tile_X0Y0_FrameStrobe_O[9]
    DIRECTION OUTPUT ;
    USE SIGNAL ;
    ANTENNADIFFAREA 2.724000 ;
    PORT
      LAYER Metal2 ;
        RECT 103.000 54.200 103.400 54.600 ;
    END
  END Tile_X0Y0_FrameStrobe_O[9]
  PIN Tile_X0Y0_N1END[0]
    DIRECTION INPUT ;
    USE SIGNAL ;
    ANTENNAGATEAREA 0.180700 ;
    ANTENNADIFFAREA 2.015400 ;
    PORT
      LAYER Metal2 ;
        RECT 2.200 0.000 2.600 0.400 ;
    END
  END Tile_X0Y0_N1END[0]
  PIN Tile_X0Y0_N1END[1]
    DIRECTION INPUT ;
    USE SIGNAL ;
    ANTENNAGATEAREA 0.180700 ;
    ANTENNADIFFAREA 2.015400 ;
    PORT
      LAYER Metal2 ;
        RECT 3.160 0.000 3.560 0.400 ;
    END
  END Tile_X0Y0_N1END[1]
  PIN Tile_X0Y0_N1END[2]
    DIRECTION INPUT ;
    USE SIGNAL ;
    ANTENNAGATEAREA 0.180700 ;
    ANTENNADIFFAREA 2.015400 ;
    PORT
      LAYER Metal2 ;
        RECT 4.120 0.000 4.520 0.400 ;
    END
  END Tile_X0Y0_N1END[2]
  PIN Tile_X0Y0_N1END[3]
    DIRECTION INPUT ;
    USE SIGNAL ;
    ANTENNAGATEAREA 0.180700 ;
    ANTENNADIFFAREA 2.015400 ;
    PORT
      LAYER Metal2 ;
        RECT 5.080 0.000 5.480 0.400 ;
    END
  END Tile_X0Y0_N1END[3]
  PIN Tile_X0Y0_N2END[0]
    DIRECTION INPUT ;
    USE SIGNAL ;
    ANTENNAGATEAREA 0.180700 ;
    ANTENNADIFFAREA 2.015400 ;
    PORT
      LAYER Metal2 ;
        RECT 24.280 0.000 24.680 0.400 ;
    END
  END Tile_X0Y0_N2END[0]
  PIN Tile_X0Y0_N2END[1]
    DIRECTION INPUT ;
    USE SIGNAL ;
    ANTENNAGATEAREA 0.180700 ;
    ANTENNADIFFAREA 2.015400 ;
    PORT
      LAYER Metal2 ;
        RECT 25.240 0.000 25.640 0.400 ;
    END
  END Tile_X0Y0_N2END[1]
  PIN Tile_X0Y0_N2END[2]
    DIRECTION INPUT ;
    USE SIGNAL ;
    ANTENNAGATEAREA 0.180700 ;
    ANTENNADIFFAREA 2.015400 ;
    PORT
      LAYER Metal2 ;
        RECT 26.200 0.000 26.600 0.400 ;
    END
  END Tile_X0Y0_N2END[2]
  PIN Tile_X0Y0_N2END[3]
    DIRECTION INPUT ;
    USE SIGNAL ;
    ANTENNAGATEAREA 0.180700 ;
    ANTENNADIFFAREA 2.015400 ;
    PORT
      LAYER Metal2 ;
        RECT 27.160 0.000 27.560 0.400 ;
    END
  END Tile_X0Y0_N2END[3]
  PIN Tile_X0Y0_N2END[4]
    DIRECTION INPUT ;
    USE SIGNAL ;
    ANTENNAGATEAREA 0.180700 ;
    ANTENNADIFFAREA 2.015400 ;
    PORT
      LAYER Metal2 ;
        RECT 28.120 0.000 28.520 0.400 ;
    END
  END Tile_X0Y0_N2END[4]
  PIN Tile_X0Y0_N2END[5]
    DIRECTION INPUT ;
    USE SIGNAL ;
    ANTENNAGATEAREA 0.180700 ;
    ANTENNADIFFAREA 2.015400 ;
    PORT
      LAYER Metal2 ;
        RECT 29.080 0.000 29.480 0.400 ;
    END
  END Tile_X0Y0_N2END[5]
  PIN Tile_X0Y0_N2END[6]
    DIRECTION INPUT ;
    USE SIGNAL ;
    ANTENNAGATEAREA 0.180700 ;
    ANTENNADIFFAREA 2.015400 ;
    PORT
      LAYER Metal2 ;
        RECT 30.040 0.000 30.440 0.400 ;
    END
  END Tile_X0Y0_N2END[6]
  PIN Tile_X0Y0_N2END[7]
    DIRECTION INPUT ;
    USE SIGNAL ;
    ANTENNAGATEAREA 0.180700 ;
    ANTENNADIFFAREA 2.015400 ;
    PORT
      LAYER Metal2 ;
        RECT 31.000 0.000 31.400 0.400 ;
    END
  END Tile_X0Y0_N2END[7]
  PIN Tile_X0Y0_N2MID[0]
    DIRECTION INPUT ;
    USE SIGNAL ;
    ANTENNAGATEAREA 0.180700 ;
    ANTENNADIFFAREA 2.015400 ;
    PORT
      LAYER Metal2 ;
        RECT 10.840 0.000 11.240 0.400 ;
    END
  END Tile_X0Y0_N2MID[0]
  PIN Tile_X0Y0_N2MID[1]
    DIRECTION INPUT ;
    USE SIGNAL ;
    ANTENNAGATEAREA 0.180700 ;
    ANTENNADIFFAREA 2.015400 ;
    PORT
      LAYER Metal2 ;
        RECT 11.800 0.000 12.200 0.400 ;
    END
  END Tile_X0Y0_N2MID[1]
  PIN Tile_X0Y0_N2MID[2]
    DIRECTION INPUT ;
    USE SIGNAL ;
    ANTENNAGATEAREA 0.180700 ;
    ANTENNADIFFAREA 2.015400 ;
    PORT
      LAYER Metal2 ;
        RECT 12.760 0.000 13.160 0.400 ;
    END
  END Tile_X0Y0_N2MID[2]
  PIN Tile_X0Y0_N2MID[3]
    DIRECTION INPUT ;
    USE SIGNAL ;
    ANTENNAGATEAREA 0.180700 ;
    ANTENNADIFFAREA 2.015400 ;
    PORT
      LAYER Metal2 ;
        RECT 13.720 0.000 14.120 0.400 ;
    END
  END Tile_X0Y0_N2MID[3]
  PIN Tile_X0Y0_N2MID[4]
    DIRECTION INPUT ;
    USE SIGNAL ;
    ANTENNAGATEAREA 0.180700 ;
    ANTENNADIFFAREA 2.015400 ;
    PORT
      LAYER Metal2 ;
        RECT 14.680 0.000 15.080 0.400 ;
    END
  END Tile_X0Y0_N2MID[4]
  PIN Tile_X0Y0_N2MID[5]
    DIRECTION INPUT ;
    USE SIGNAL ;
    ANTENNAGATEAREA 0.180700 ;
    ANTENNADIFFAREA 2.015400 ;
    PORT
      LAYER Metal2 ;
        RECT 15.640 0.000 16.040 0.400 ;
    END
  END Tile_X0Y0_N2MID[5]
  PIN Tile_X0Y0_N2MID[6]
    DIRECTION INPUT ;
    USE SIGNAL ;
    ANTENNAGATEAREA 0.180700 ;
    ANTENNADIFFAREA 2.015400 ;
    PORT
      LAYER Metal2 ;
        RECT 16.600 0.000 17.000 0.400 ;
    END
  END Tile_X0Y0_N2MID[6]
  PIN Tile_X0Y0_N2MID[7]
    DIRECTION INPUT ;
    USE SIGNAL ;
    ANTENNAGATEAREA 0.180700 ;
    ANTENNADIFFAREA 2.015400 ;
    PORT
      LAYER Metal2 ;
        RECT 17.560 0.000 17.960 0.400 ;
    END
  END Tile_X0Y0_N2MID[7]
  PIN Tile_X0Y0_N4END[0]
    DIRECTION INPUT ;
    USE SIGNAL ;
    ANTENNAGATEAREA 0.180700 ;
    ANTENNADIFFAREA 2.015400 ;
    PORT
      LAYER Metal2 ;
        RECT 40.600 0.000 41.000 0.400 ;
    END
  END Tile_X0Y0_N4END[0]
  PIN Tile_X0Y0_N4END[10]
    DIRECTION INPUT ;
    USE SIGNAL ;
    ANTENNAGATEAREA 0.180700 ;
    ANTENNADIFFAREA 2.015400 ;
    PORT
      LAYER Metal2 ;
        RECT 50.200 0.000 50.600 0.400 ;
    END
  END Tile_X0Y0_N4END[10]
  PIN Tile_X0Y0_N4END[11]
    DIRECTION INPUT ;
    USE SIGNAL ;
    ANTENNAGATEAREA 0.180700 ;
    ANTENNADIFFAREA 2.015400 ;
    PORT
      LAYER Metal2 ;
        RECT 51.160 0.000 51.560 0.400 ;
    END
  END Tile_X0Y0_N4END[11]
  PIN Tile_X0Y0_N4END[12]
    DIRECTION INPUT ;
    USE SIGNAL ;
    ANTENNAGATEAREA 0.180700 ;
    ANTENNADIFFAREA 2.015400 ;
    PORT
      LAYER Metal2 ;
        RECT 52.120 0.000 52.520 0.400 ;
    END
  END Tile_X0Y0_N4END[12]
  PIN Tile_X0Y0_N4END[13]
    DIRECTION INPUT ;
    USE SIGNAL ;
    ANTENNAGATEAREA 0.180700 ;
    ANTENNADIFFAREA 2.015400 ;
    PORT
      LAYER Metal2 ;
        RECT 53.080 0.000 53.480 0.400 ;
    END
  END Tile_X0Y0_N4END[13]
  PIN Tile_X0Y0_N4END[14]
    DIRECTION INPUT ;
    USE SIGNAL ;
    ANTENNAGATEAREA 0.180700 ;
    ANTENNADIFFAREA 2.015400 ;
    PORT
      LAYER Metal2 ;
        RECT 54.040 0.000 54.440 0.400 ;
    END
  END Tile_X0Y0_N4END[14]
  PIN Tile_X0Y0_N4END[15]
    DIRECTION INPUT ;
    USE SIGNAL ;
    ANTENNAGATEAREA 0.180700 ;
    ANTENNADIFFAREA 2.015400 ;
    PORT
      LAYER Metal2 ;
        RECT 55.000 0.000 55.400 0.400 ;
    END
  END Tile_X0Y0_N4END[15]
  PIN Tile_X0Y0_N4END[1]
    DIRECTION INPUT ;
    USE SIGNAL ;
    ANTENNAGATEAREA 0.180700 ;
    ANTENNADIFFAREA 2.015400 ;
    PORT
      LAYER Metal2 ;
        RECT 41.560 0.000 41.960 0.400 ;
    END
  END Tile_X0Y0_N4END[1]
  PIN Tile_X0Y0_N4END[2]
    DIRECTION INPUT ;
    USE SIGNAL ;
    ANTENNAGATEAREA 0.180700 ;
    ANTENNADIFFAREA 2.015400 ;
    PORT
      LAYER Metal2 ;
        RECT 42.520 0.000 42.920 0.400 ;
    END
  END Tile_X0Y0_N4END[2]
  PIN Tile_X0Y0_N4END[3]
    DIRECTION INPUT ;
    USE SIGNAL ;
    ANTENNAGATEAREA 0.180700 ;
    ANTENNADIFFAREA 2.015400 ;
    PORT
      LAYER Metal2 ;
        RECT 43.480 0.000 43.880 0.400 ;
    END
  END Tile_X0Y0_N4END[3]
  PIN Tile_X0Y0_N4END[4]
    DIRECTION INPUT ;
    USE SIGNAL ;
    ANTENNAGATEAREA 0.180700 ;
    ANTENNADIFFAREA 2.015400 ;
    PORT
      LAYER Metal2 ;
        RECT 44.440 0.000 44.840 0.400 ;
    END
  END Tile_X0Y0_N4END[4]
  PIN Tile_X0Y0_N4END[5]
    DIRECTION INPUT ;
    USE SIGNAL ;
    ANTENNAGATEAREA 0.180700 ;
    ANTENNADIFFAREA 2.015400 ;
    PORT
      LAYER Metal2 ;
        RECT 45.400 0.000 45.800 0.400 ;
    END
  END Tile_X0Y0_N4END[5]
  PIN Tile_X0Y0_N4END[6]
    DIRECTION INPUT ;
    USE SIGNAL ;
    ANTENNAGATEAREA 0.180700 ;
    ANTENNADIFFAREA 2.015400 ;
    PORT
      LAYER Metal2 ;
        RECT 46.360 0.000 46.760 0.400 ;
    END
  END Tile_X0Y0_N4END[6]
  PIN Tile_X0Y0_N4END[7]
    DIRECTION INPUT ;
    USE SIGNAL ;
    ANTENNAGATEAREA 0.180700 ;
    ANTENNADIFFAREA 2.015400 ;
    PORT
      LAYER Metal2 ;
        RECT 47.320 0.000 47.720 0.400 ;
    END
  END Tile_X0Y0_N4END[7]
  PIN Tile_X0Y0_N4END[8]
    DIRECTION INPUT ;
    USE SIGNAL ;
    ANTENNAGATEAREA 0.180700 ;
    ANTENNADIFFAREA 2.015400 ;
    PORT
      LAYER Metal2 ;
        RECT 48.280 0.000 48.680 0.400 ;
    END
  END Tile_X0Y0_N4END[8]
  PIN Tile_X0Y0_N4END[9]
    DIRECTION INPUT ;
    USE SIGNAL ;
    ANTENNAGATEAREA 0.180700 ;
    ANTENNADIFFAREA 2.015400 ;
    PORT
      LAYER Metal2 ;
        RECT 49.240 0.000 49.640 0.400 ;
    END
  END Tile_X0Y0_N4END[9]
  PIN Tile_X0Y0_NN4END[0]
    DIRECTION INPUT ;
    USE SIGNAL ;
    ANTENNAGATEAREA 0.361400 ;
    ANTENNADIFFAREA 4.030800 ;
    PORT
      LAYER Metal2 ;
        RECT 68.440 0.000 68.840 0.400 ;
    END
  END Tile_X0Y0_NN4END[0]
  PIN Tile_X0Y0_NN4END[10]
    DIRECTION INPUT ;
    USE SIGNAL ;
    ANTENNAGATEAREA 0.361400 ;
    ANTENNADIFFAREA 4.030800 ;
    PORT
      LAYER Metal2 ;
        RECT 78.040 0.000 78.440 0.400 ;
    END
  END Tile_X0Y0_NN4END[10]
  PIN Tile_X0Y0_NN4END[11]
    DIRECTION INPUT ;
    USE SIGNAL ;
    ANTENNAGATEAREA 0.361400 ;
    ANTENNADIFFAREA 4.030800 ;
    PORT
      LAYER Metal2 ;
        RECT 79.000 0.000 79.400 0.400 ;
    END
  END Tile_X0Y0_NN4END[11]
  PIN Tile_X0Y0_NN4END[12]
    DIRECTION INPUT ;
    USE SIGNAL ;
    ANTENNAGATEAREA 0.361400 ;
    ANTENNADIFFAREA 4.030800 ;
    PORT
      LAYER Metal2 ;
        RECT 79.960 0.000 80.360 0.400 ;
    END
  END Tile_X0Y0_NN4END[12]
  PIN Tile_X0Y0_NN4END[13]
    DIRECTION INPUT ;
    USE SIGNAL ;
    ANTENNAGATEAREA 0.361400 ;
    ANTENNADIFFAREA 4.030800 ;
    PORT
      LAYER Metal2 ;
        RECT 80.920 0.000 81.320 0.400 ;
    END
  END Tile_X0Y0_NN4END[13]
  PIN Tile_X0Y0_NN4END[14]
    DIRECTION INPUT ;
    USE SIGNAL ;
    ANTENNAGATEAREA 0.361400 ;
    ANTENNADIFFAREA 4.030800 ;
    PORT
      LAYER Metal2 ;
        RECT 81.880 0.000 82.280 0.400 ;
    END
  END Tile_X0Y0_NN4END[14]
  PIN Tile_X0Y0_NN4END[15]
    DIRECTION INPUT ;
    USE SIGNAL ;
    ANTENNAGATEAREA 0.361400 ;
    ANTENNADIFFAREA 4.030800 ;
    PORT
      LAYER Metal2 ;
        RECT 82.840 0.000 83.240 0.400 ;
    END
  END Tile_X0Y0_NN4END[15]
  PIN Tile_X0Y0_NN4END[1]
    DIRECTION INPUT ;
    USE SIGNAL ;
    ANTENNAGATEAREA 0.361400 ;
    ANTENNADIFFAREA 4.030800 ;
    PORT
      LAYER Metal2 ;
        RECT 69.400 0.000 69.800 0.400 ;
    END
  END Tile_X0Y0_NN4END[1]
  PIN Tile_X0Y0_NN4END[2]
    DIRECTION INPUT ;
    USE SIGNAL ;
    ANTENNAGATEAREA 0.361400 ;
    ANTENNADIFFAREA 4.030800 ;
    PORT
      LAYER Metal2 ;
        RECT 70.360 0.000 70.760 0.400 ;
    END
  END Tile_X0Y0_NN4END[2]
  PIN Tile_X0Y0_NN4END[3]
    DIRECTION INPUT ;
    USE SIGNAL ;
    ANTENNAGATEAREA 0.361400 ;
    ANTENNADIFFAREA 4.030800 ;
    PORT
      LAYER Metal2 ;
        RECT 71.320 0.000 71.720 0.400 ;
    END
  END Tile_X0Y0_NN4END[3]
  PIN Tile_X0Y0_NN4END[4]
    DIRECTION INPUT ;
    USE SIGNAL ;
    ANTENNAGATEAREA 0.361400 ;
    ANTENNADIFFAREA 4.030800 ;
    PORT
      LAYER Metal2 ;
        RECT 72.280 0.000 72.680 0.400 ;
    END
  END Tile_X0Y0_NN4END[4]
  PIN Tile_X0Y0_NN4END[5]
    DIRECTION INPUT ;
    USE SIGNAL ;
    ANTENNAGATEAREA 0.361400 ;
    ANTENNADIFFAREA 4.030800 ;
    PORT
      LAYER Metal2 ;
        RECT 73.240 0.000 73.640 0.400 ;
    END
  END Tile_X0Y0_NN4END[5]
  PIN Tile_X0Y0_NN4END[6]
    DIRECTION INPUT ;
    USE SIGNAL ;
    ANTENNAGATEAREA 0.361400 ;
    ANTENNADIFFAREA 4.030800 ;
    PORT
      LAYER Metal2 ;
        RECT 74.200 0.000 74.600 0.400 ;
    END
  END Tile_X0Y0_NN4END[6]
  PIN Tile_X0Y0_NN4END[7]
    DIRECTION INPUT ;
    USE SIGNAL ;
    ANTENNAGATEAREA 0.361400 ;
    ANTENNADIFFAREA 4.030800 ;
    PORT
      LAYER Metal2 ;
        RECT 75.160 0.000 75.560 0.400 ;
    END
  END Tile_X0Y0_NN4END[7]
  PIN Tile_X0Y0_NN4END[8]
    DIRECTION INPUT ;
    USE SIGNAL ;
    ANTENNAGATEAREA 0.361400 ;
    ANTENNADIFFAREA 4.030800 ;
    PORT
      LAYER Metal2 ;
        RECT 76.120 0.000 76.520 0.400 ;
    END
  END Tile_X0Y0_NN4END[8]
  PIN Tile_X0Y0_NN4END[9]
    DIRECTION INPUT ;
    USE SIGNAL ;
    ANTENNAGATEAREA 0.361400 ;
    ANTENNADIFFAREA 4.030800 ;
    PORT
      LAYER Metal2 ;
        RECT 77.080 0.000 77.480 0.400 ;
    END
  END Tile_X0Y0_NN4END[9]
  PIN Tile_X0Y0_S1BEG[0]
    DIRECTION OUTPUT ;
    USE SIGNAL ;
    ANTENNADIFFAREA 2.724000 ;
    PORT
      LAYER Metal2 ;
        RECT 90.520 0.000 90.920 0.400 ;
    END
  END Tile_X0Y0_S1BEG[0]
  PIN Tile_X0Y0_S1BEG[1]
    DIRECTION OUTPUT ;
    USE SIGNAL ;
    ANTENNADIFFAREA 2.724000 ;
    PORT
      LAYER Metal2 ;
        RECT 91.480 0.000 91.880 0.400 ;
    END
  END Tile_X0Y0_S1BEG[1]
  PIN Tile_X0Y0_S1BEG[2]
    DIRECTION OUTPUT ;
    USE SIGNAL ;
    ANTENNADIFFAREA 2.724000 ;
    PORT
      LAYER Metal2 ;
        RECT 92.440 0.000 92.840 0.400 ;
    END
  END Tile_X0Y0_S1BEG[2]
  PIN Tile_X0Y0_S1BEG[3]
    DIRECTION OUTPUT ;
    USE SIGNAL ;
    ANTENNADIFFAREA 2.724000 ;
    PORT
      LAYER Metal2 ;
        RECT 93.400 0.000 93.800 0.400 ;
    END
  END Tile_X0Y0_S1BEG[3]
  PIN Tile_X0Y0_S2BEG[0]
    DIRECTION OUTPUT ;
    USE SIGNAL ;
    ANTENNADIFFAREA 2.724000 ;
    PORT
      LAYER Metal2 ;
        RECT 99.160 0.000 99.560 0.400 ;
    END
  END Tile_X0Y0_S2BEG[0]
  PIN Tile_X0Y0_S2BEG[1]
    DIRECTION OUTPUT ;
    USE SIGNAL ;
    ANTENNADIFFAREA 2.724000 ;
    PORT
      LAYER Metal2 ;
        RECT 100.120 0.000 100.520 0.400 ;
    END
  END Tile_X0Y0_S2BEG[1]
  PIN Tile_X0Y0_S2BEG[2]
    DIRECTION OUTPUT ;
    USE SIGNAL ;
    ANTENNADIFFAREA 2.724000 ;
    PORT
      LAYER Metal2 ;
        RECT 101.080 0.000 101.480 0.400 ;
    END
  END Tile_X0Y0_S2BEG[2]
  PIN Tile_X0Y0_S2BEG[3]
    DIRECTION OUTPUT ;
    USE SIGNAL ;
    ANTENNADIFFAREA 2.724000 ;
    PORT
      LAYER Metal2 ;
        RECT 102.040 0.000 102.440 0.400 ;
    END
  END Tile_X0Y0_S2BEG[3]
  PIN Tile_X0Y0_S2BEG[4]
    DIRECTION OUTPUT ;
    USE SIGNAL ;
    ANTENNADIFFAREA 2.724000 ;
    PORT
      LAYER Metal2 ;
        RECT 103.000 0.000 103.400 0.400 ;
    END
  END Tile_X0Y0_S2BEG[4]
  PIN Tile_X0Y0_S2BEG[5]
    DIRECTION OUTPUT ;
    USE SIGNAL ;
    ANTENNADIFFAREA 2.724000 ;
    PORT
      LAYER Metal2 ;
        RECT 103.960 0.000 104.360 0.400 ;
    END
  END Tile_X0Y0_S2BEG[5]
  PIN Tile_X0Y0_S2BEG[6]
    DIRECTION OUTPUT ;
    USE SIGNAL ;
    ANTENNADIFFAREA 2.724000 ;
    PORT
      LAYER Metal2 ;
        RECT 104.920 0.000 105.320 0.400 ;
    END
  END Tile_X0Y0_S2BEG[6]
  PIN Tile_X0Y0_S2BEG[7]
    DIRECTION OUTPUT ;
    USE SIGNAL ;
    ANTENNADIFFAREA 2.724000 ;
    PORT
      LAYER Metal2 ;
        RECT 105.880 0.000 106.280 0.400 ;
    END
  END Tile_X0Y0_S2BEG[7]
  PIN Tile_X0Y0_S2BEGb[0]
    DIRECTION OUTPUT ;
    USE SIGNAL ;
    ANTENNADIFFAREA 2.724000 ;
    PORT
      LAYER Metal2 ;
        RECT 113.560 0.000 113.960 0.400 ;
    END
  END Tile_X0Y0_S2BEGb[0]
  PIN Tile_X0Y0_S2BEGb[1]
    DIRECTION OUTPUT ;
    USE SIGNAL ;
    ANTENNADIFFAREA 2.724000 ;
    PORT
      LAYER Metal2 ;
        RECT 114.520 0.000 114.920 0.400 ;
    END
  END Tile_X0Y0_S2BEGb[1]
  PIN Tile_X0Y0_S2BEGb[2]
    DIRECTION OUTPUT ;
    USE SIGNAL ;
    ANTENNADIFFAREA 2.724000 ;
    PORT
      LAYER Metal2 ;
        RECT 115.480 0.000 115.880 0.400 ;
    END
  END Tile_X0Y0_S2BEGb[2]
  PIN Tile_X0Y0_S2BEGb[3]
    DIRECTION OUTPUT ;
    USE SIGNAL ;
    ANTENNADIFFAREA 2.724000 ;
    PORT
      LAYER Metal2 ;
        RECT 116.440 0.000 116.840 0.400 ;
    END
  END Tile_X0Y0_S2BEGb[3]
  PIN Tile_X0Y0_S2BEGb[4]
    DIRECTION OUTPUT ;
    USE SIGNAL ;
    ANTENNADIFFAREA 2.724000 ;
    PORT
      LAYER Metal2 ;
        RECT 117.400 0.000 117.800 0.400 ;
    END
  END Tile_X0Y0_S2BEGb[4]
  PIN Tile_X0Y0_S2BEGb[5]
    DIRECTION OUTPUT ;
    USE SIGNAL ;
    ANTENNADIFFAREA 2.724000 ;
    PORT
      LAYER Metal2 ;
        RECT 118.360 0.000 118.760 0.400 ;
    END
  END Tile_X0Y0_S2BEGb[5]
  PIN Tile_X0Y0_S2BEGb[6]
    DIRECTION OUTPUT ;
    USE SIGNAL ;
    ANTENNADIFFAREA 2.724000 ;
    PORT
      LAYER Metal2 ;
        RECT 119.320 0.000 119.720 0.400 ;
    END
  END Tile_X0Y0_S2BEGb[6]
  PIN Tile_X0Y0_S2BEGb[7]
    DIRECTION OUTPUT ;
    USE SIGNAL ;
    ANTENNADIFFAREA 2.724000 ;
    PORT
      LAYER Metal2 ;
        RECT 120.280 0.000 120.680 0.400 ;
    END
  END Tile_X0Y0_S2BEGb[7]
  PIN Tile_X0Y0_S4BEG[0]
    DIRECTION OUTPUT ;
    USE SIGNAL ;
    ANTENNADIFFAREA 2.724000 ;
    PORT
      LAYER Metal2 ;
        RECT 129.880 0.000 130.280 0.400 ;
    END
  END Tile_X0Y0_S4BEG[0]
  PIN Tile_X0Y0_S4BEG[10]
    DIRECTION OUTPUT ;
    USE SIGNAL ;
    ANTENNADIFFAREA 2.724000 ;
    PORT
      LAYER Metal2 ;
        RECT 139.480 0.000 139.880 0.400 ;
    END
  END Tile_X0Y0_S4BEG[10]
  PIN Tile_X0Y0_S4BEG[11]
    DIRECTION OUTPUT ;
    USE SIGNAL ;
    ANTENNADIFFAREA 2.724000 ;
    PORT
      LAYER Metal2 ;
        RECT 140.440 0.000 140.840 0.400 ;
    END
  END Tile_X0Y0_S4BEG[11]
  PIN Tile_X0Y0_S4BEG[12]
    DIRECTION OUTPUT ;
    USE SIGNAL ;
    ANTENNADIFFAREA 2.724000 ;
    PORT
      LAYER Metal2 ;
        RECT 141.400 0.000 141.800 0.400 ;
    END
  END Tile_X0Y0_S4BEG[12]
  PIN Tile_X0Y0_S4BEG[13]
    DIRECTION OUTPUT ;
    USE SIGNAL ;
    ANTENNADIFFAREA 2.724000 ;
    PORT
      LAYER Metal2 ;
        RECT 142.360 0.000 142.760 0.400 ;
    END
  END Tile_X0Y0_S4BEG[13]
  PIN Tile_X0Y0_S4BEG[14]
    DIRECTION OUTPUT ;
    USE SIGNAL ;
    ANTENNADIFFAREA 2.724000 ;
    PORT
      LAYER Metal2 ;
        RECT 143.320 0.000 143.720 0.400 ;
    END
  END Tile_X0Y0_S4BEG[14]
  PIN Tile_X0Y0_S4BEG[15]
    DIRECTION OUTPUT ;
    USE SIGNAL ;
    ANTENNADIFFAREA 2.724000 ;
    PORT
      LAYER Metal2 ;
        RECT 144.280 0.000 144.680 0.400 ;
    END
  END Tile_X0Y0_S4BEG[15]
  PIN Tile_X0Y0_S4BEG[1]
    DIRECTION OUTPUT ;
    USE SIGNAL ;
    ANTENNADIFFAREA 2.724000 ;
    PORT
      LAYER Metal2 ;
        RECT 130.840 0.000 131.240 0.400 ;
    END
  END Tile_X0Y0_S4BEG[1]
  PIN Tile_X0Y0_S4BEG[2]
    DIRECTION OUTPUT ;
    USE SIGNAL ;
    ANTENNADIFFAREA 2.724000 ;
    PORT
      LAYER Metal2 ;
        RECT 131.800 0.000 132.200 0.400 ;
    END
  END Tile_X0Y0_S4BEG[2]
  PIN Tile_X0Y0_S4BEG[3]
    DIRECTION OUTPUT ;
    USE SIGNAL ;
    ANTENNADIFFAREA 2.724000 ;
    PORT
      LAYER Metal2 ;
        RECT 132.760 0.000 133.160 0.400 ;
    END
  END Tile_X0Y0_S4BEG[3]
  PIN Tile_X0Y0_S4BEG[4]
    DIRECTION OUTPUT ;
    USE SIGNAL ;
    ANTENNADIFFAREA 2.724000 ;
    PORT
      LAYER Metal2 ;
        RECT 133.720 0.000 134.120 0.400 ;
    END
  END Tile_X0Y0_S4BEG[4]
  PIN Tile_X0Y0_S4BEG[5]
    DIRECTION OUTPUT ;
    USE SIGNAL ;
    ANTENNADIFFAREA 2.724000 ;
    PORT
      LAYER Metal2 ;
        RECT 134.680 0.000 135.080 0.400 ;
    END
  END Tile_X0Y0_S4BEG[5]
  PIN Tile_X0Y0_S4BEG[6]
    DIRECTION OUTPUT ;
    USE SIGNAL ;
    ANTENNADIFFAREA 2.724000 ;
    PORT
      LAYER Metal2 ;
        RECT 135.640 0.000 136.040 0.400 ;
    END
  END Tile_X0Y0_S4BEG[6]
  PIN Tile_X0Y0_S4BEG[7]
    DIRECTION OUTPUT ;
    USE SIGNAL ;
    ANTENNADIFFAREA 2.724000 ;
    PORT
      LAYER Metal2 ;
        RECT 136.600 0.000 137.000 0.400 ;
    END
  END Tile_X0Y0_S4BEG[7]
  PIN Tile_X0Y0_S4BEG[8]
    DIRECTION OUTPUT ;
    USE SIGNAL ;
    ANTENNADIFFAREA 2.724000 ;
    PORT
      LAYER Metal2 ;
        RECT 137.560 0.000 137.960 0.400 ;
    END
  END Tile_X0Y0_S4BEG[8]
  PIN Tile_X0Y0_S4BEG[9]
    DIRECTION OUTPUT ;
    USE SIGNAL ;
    ANTENNADIFFAREA 2.724000 ;
    PORT
      LAYER Metal2 ;
        RECT 138.520 0.000 138.920 0.400 ;
    END
  END Tile_X0Y0_S4BEG[9]
  PIN Tile_X0Y0_SS4BEG[0]
    DIRECTION OUTPUT ;
    USE SIGNAL ;
    ANTENNADIFFAREA 2.724000 ;
    PORT
      LAYER Metal2 ;
        RECT 157.720 0.000 158.120 0.400 ;
    END
  END Tile_X0Y0_SS4BEG[0]
  PIN Tile_X0Y0_SS4BEG[10]
    DIRECTION OUTPUT ;
    USE SIGNAL ;
    ANTENNADIFFAREA 2.724000 ;
    PORT
      LAYER Metal2 ;
        RECT 167.320 0.000 167.720 0.400 ;
    END
  END Tile_X0Y0_SS4BEG[10]
  PIN Tile_X0Y0_SS4BEG[11]
    DIRECTION OUTPUT ;
    USE SIGNAL ;
    ANTENNADIFFAREA 2.724000 ;
    PORT
      LAYER Metal2 ;
        RECT 168.280 0.000 168.680 0.400 ;
    END
  END Tile_X0Y0_SS4BEG[11]
  PIN Tile_X0Y0_SS4BEG[12]
    DIRECTION OUTPUT ;
    USE SIGNAL ;
    ANTENNADIFFAREA 2.724000 ;
    PORT
      LAYER Metal2 ;
        RECT 169.240 0.000 169.640 0.400 ;
    END
  END Tile_X0Y0_SS4BEG[12]
  PIN Tile_X0Y0_SS4BEG[13]
    DIRECTION OUTPUT ;
    USE SIGNAL ;
    ANTENNADIFFAREA 2.724000 ;
    PORT
      LAYER Metal2 ;
        RECT 170.200 0.000 170.600 0.400 ;
    END
  END Tile_X0Y0_SS4BEG[13]
  PIN Tile_X0Y0_SS4BEG[14]
    DIRECTION OUTPUT ;
    USE SIGNAL ;
    ANTENNADIFFAREA 2.724000 ;
    PORT
      LAYER Metal2 ;
        RECT 171.160 0.000 171.560 0.400 ;
    END
  END Tile_X0Y0_SS4BEG[14]
  PIN Tile_X0Y0_SS4BEG[15]
    DIRECTION OUTPUT ;
    USE SIGNAL ;
    ANTENNADIFFAREA 2.724000 ;
    PORT
      LAYER Metal2 ;
        RECT 172.120 0.000 172.520 0.400 ;
    END
  END Tile_X0Y0_SS4BEG[15]
  PIN Tile_X0Y0_SS4BEG[1]
    DIRECTION OUTPUT ;
    USE SIGNAL ;
    ANTENNADIFFAREA 2.724000 ;
    PORT
      LAYER Metal2 ;
        RECT 158.680 0.000 159.080 0.400 ;
    END
  END Tile_X0Y0_SS4BEG[1]
  PIN Tile_X0Y0_SS4BEG[2]
    DIRECTION OUTPUT ;
    USE SIGNAL ;
    ANTENNADIFFAREA 2.724000 ;
    PORT
      LAYER Metal2 ;
        RECT 159.640 0.000 160.040 0.400 ;
    END
  END Tile_X0Y0_SS4BEG[2]
  PIN Tile_X0Y0_SS4BEG[3]
    DIRECTION OUTPUT ;
    USE SIGNAL ;
    ANTENNADIFFAREA 2.724000 ;
    PORT
      LAYER Metal2 ;
        RECT 160.600 0.000 161.000 0.400 ;
    END
  END Tile_X0Y0_SS4BEG[3]
  PIN Tile_X0Y0_SS4BEG[4]
    DIRECTION OUTPUT ;
    USE SIGNAL ;
    ANTENNADIFFAREA 2.724000 ;
    PORT
      LAYER Metal2 ;
        RECT 161.560 0.000 161.960 0.400 ;
    END
  END Tile_X0Y0_SS4BEG[4]
  PIN Tile_X0Y0_SS4BEG[5]
    DIRECTION OUTPUT ;
    USE SIGNAL ;
    ANTENNADIFFAREA 2.724000 ;
    PORT
      LAYER Metal2 ;
        RECT 162.520 0.000 162.920 0.400 ;
    END
  END Tile_X0Y0_SS4BEG[5]
  PIN Tile_X0Y0_SS4BEG[6]
    DIRECTION OUTPUT ;
    USE SIGNAL ;
    ANTENNADIFFAREA 2.724000 ;
    PORT
      LAYER Metal2 ;
        RECT 163.480 0.000 163.880 0.400 ;
    END
  END Tile_X0Y0_SS4BEG[6]
  PIN Tile_X0Y0_SS4BEG[7]
    DIRECTION OUTPUT ;
    USE SIGNAL ;
    ANTENNADIFFAREA 2.724000 ;
    PORT
      LAYER Metal2 ;
        RECT 164.440 0.000 164.840 0.400 ;
    END
  END Tile_X0Y0_SS4BEG[7]
  PIN Tile_X0Y0_SS4BEG[8]
    DIRECTION OUTPUT ;
    USE SIGNAL ;
    ANTENNADIFFAREA 2.724000 ;
    PORT
      LAYER Metal2 ;
        RECT 165.400 0.000 165.800 0.400 ;
    END
  END Tile_X0Y0_SS4BEG[8]
  PIN Tile_X0Y0_SS4BEG[9]
    DIRECTION OUTPUT ;
    USE SIGNAL ;
    ANTENNADIFFAREA 2.724000 ;
    PORT
      LAYER Metal2 ;
        RECT 166.360 0.000 166.760 0.400 ;
    END
  END Tile_X0Y0_SS4BEG[9]
  PIN Tile_X0Y0_UserCLK
    DIRECTION INPUT ;
    USE SIGNAL ;
    ANTENNAGATEAREA 0.180700 ;
    ANTENNADIFFAREA 2.015400 ;
    PORT
      LAYER Metal3 ;
        RECT 0.000 1.060 0.400 1.460 ;
    END
  END Tile_X0Y0_UserCLK
  PIN Tile_X1Y0_Ci
    DIRECTION INPUT ;
    USE SIGNAL ;
    PORT
      LAYER Metal2 ;
        RECT 395.800 0.000 396.200 0.400 ;
    END
  END Tile_X1Y0_Ci
  PIN Tile_X1Y0_FrameData_O[0]
    DIRECTION OUTPUT ;
    USE SIGNAL ;
    ANTENNADIFFAREA 2.724000 ;
    PORT
      LAYER Metal3 ;
        RECT 431.600 15.340 432.000 15.740 ;
    END
  END Tile_X1Y0_FrameData_O[0]
  PIN Tile_X1Y0_FrameData_O[10]
    DIRECTION OUTPUT ;
    USE SIGNAL ;
    ANTENNADIFFAREA 2.724000 ;
    PORT
      LAYER Metal3 ;
        RECT 431.600 23.740 432.000 24.140 ;
    END
  END Tile_X1Y0_FrameData_O[10]
  PIN Tile_X1Y0_FrameData_O[11]
    DIRECTION OUTPUT ;
    USE SIGNAL ;
    ANTENNADIFFAREA 2.724000 ;
    PORT
      LAYER Metal3 ;
        RECT 431.600 24.580 432.000 24.980 ;
    END
  END Tile_X1Y0_FrameData_O[11]
  PIN Tile_X1Y0_FrameData_O[12]
    DIRECTION OUTPUT ;
    USE SIGNAL ;
    ANTENNADIFFAREA 2.724000 ;
    PORT
      LAYER Metal3 ;
        RECT 431.600 25.420 432.000 25.820 ;
    END
  END Tile_X1Y0_FrameData_O[12]
  PIN Tile_X1Y0_FrameData_O[13]
    DIRECTION OUTPUT ;
    USE SIGNAL ;
    ANTENNADIFFAREA 2.724000 ;
    PORT
      LAYER Metal3 ;
        RECT 431.600 26.260 432.000 26.660 ;
    END
  END Tile_X1Y0_FrameData_O[13]
  PIN Tile_X1Y0_FrameData_O[14]
    DIRECTION OUTPUT ;
    USE SIGNAL ;
    ANTENNADIFFAREA 2.724000 ;
    PORT
      LAYER Metal3 ;
        RECT 431.600 27.100 432.000 27.500 ;
    END
  END Tile_X1Y0_FrameData_O[14]
  PIN Tile_X1Y0_FrameData_O[15]
    DIRECTION OUTPUT ;
    USE SIGNAL ;
    ANTENNADIFFAREA 2.724000 ;
    PORT
      LAYER Metal3 ;
        RECT 431.600 27.940 432.000 28.340 ;
    END
  END Tile_X1Y0_FrameData_O[15]
  PIN Tile_X1Y0_FrameData_O[16]
    DIRECTION OUTPUT ;
    USE SIGNAL ;
    ANTENNADIFFAREA 2.724000 ;
    PORT
      LAYER Metal3 ;
        RECT 431.600 28.780 432.000 29.180 ;
    END
  END Tile_X1Y0_FrameData_O[16]
  PIN Tile_X1Y0_FrameData_O[17]
    DIRECTION OUTPUT ;
    USE SIGNAL ;
    ANTENNADIFFAREA 2.724000 ;
    PORT
      LAYER Metal3 ;
        RECT 431.600 29.620 432.000 30.020 ;
    END
  END Tile_X1Y0_FrameData_O[17]
  PIN Tile_X1Y0_FrameData_O[18]
    DIRECTION OUTPUT ;
    USE SIGNAL ;
    ANTENNADIFFAREA 2.724000 ;
    PORT
      LAYER Metal3 ;
        RECT 431.600 30.460 432.000 30.860 ;
    END
  END Tile_X1Y0_FrameData_O[18]
  PIN Tile_X1Y0_FrameData_O[19]
    DIRECTION OUTPUT ;
    USE SIGNAL ;
    ANTENNADIFFAREA 2.724000 ;
    PORT
      LAYER Metal3 ;
        RECT 431.600 31.300 432.000 31.700 ;
    END
  END Tile_X1Y0_FrameData_O[19]
  PIN Tile_X1Y0_FrameData_O[1]
    DIRECTION OUTPUT ;
    USE SIGNAL ;
    ANTENNADIFFAREA 2.724000 ;
    PORT
      LAYER Metal3 ;
        RECT 431.600 16.180 432.000 16.580 ;
    END
  END Tile_X1Y0_FrameData_O[1]
  PIN Tile_X1Y0_FrameData_O[20]
    DIRECTION OUTPUT ;
    USE SIGNAL ;
    ANTENNADIFFAREA 2.724000 ;
    PORT
      LAYER Metal3 ;
        RECT 431.600 32.140 432.000 32.540 ;
    END
  END Tile_X1Y0_FrameData_O[20]
  PIN Tile_X1Y0_FrameData_O[21]
    DIRECTION OUTPUT ;
    USE SIGNAL ;
    ANTENNADIFFAREA 2.724000 ;
    PORT
      LAYER Metal3 ;
        RECT 431.600 32.980 432.000 33.380 ;
    END
  END Tile_X1Y0_FrameData_O[21]
  PIN Tile_X1Y0_FrameData_O[22]
    DIRECTION OUTPUT ;
    USE SIGNAL ;
    ANTENNADIFFAREA 2.724000 ;
    PORT
      LAYER Metal3 ;
        RECT 431.600 33.820 432.000 34.220 ;
    END
  END Tile_X1Y0_FrameData_O[22]
  PIN Tile_X1Y0_FrameData_O[23]
    DIRECTION OUTPUT ;
    USE SIGNAL ;
    ANTENNADIFFAREA 2.724000 ;
    PORT
      LAYER Metal3 ;
        RECT 431.600 34.660 432.000 35.060 ;
    END
  END Tile_X1Y0_FrameData_O[23]
  PIN Tile_X1Y0_FrameData_O[24]
    DIRECTION OUTPUT ;
    USE SIGNAL ;
    ANTENNADIFFAREA 2.724000 ;
    PORT
      LAYER Metal3 ;
        RECT 431.600 35.500 432.000 35.900 ;
    END
  END Tile_X1Y0_FrameData_O[24]
  PIN Tile_X1Y0_FrameData_O[25]
    DIRECTION OUTPUT ;
    USE SIGNAL ;
    ANTENNADIFFAREA 2.724000 ;
    PORT
      LAYER Metal3 ;
        RECT 431.600 36.340 432.000 36.740 ;
    END
  END Tile_X1Y0_FrameData_O[25]
  PIN Tile_X1Y0_FrameData_O[26]
    DIRECTION OUTPUT ;
    USE SIGNAL ;
    ANTENNADIFFAREA 2.724000 ;
    PORT
      LAYER Metal3 ;
        RECT 431.600 37.180 432.000 37.580 ;
    END
  END Tile_X1Y0_FrameData_O[26]
  PIN Tile_X1Y0_FrameData_O[27]
    DIRECTION OUTPUT ;
    USE SIGNAL ;
    ANTENNADIFFAREA 2.724000 ;
    PORT
      LAYER Metal3 ;
        RECT 431.600 38.020 432.000 38.420 ;
    END
  END Tile_X1Y0_FrameData_O[27]
  PIN Tile_X1Y0_FrameData_O[28]
    DIRECTION OUTPUT ;
    USE SIGNAL ;
    ANTENNADIFFAREA 2.724000 ;
    PORT
      LAYER Metal3 ;
        RECT 431.600 38.860 432.000 39.260 ;
    END
  END Tile_X1Y0_FrameData_O[28]
  PIN Tile_X1Y0_FrameData_O[29]
    DIRECTION OUTPUT ;
    USE SIGNAL ;
    ANTENNADIFFAREA 2.724000 ;
    PORT
      LAYER Metal3 ;
        RECT 431.600 39.700 432.000 40.100 ;
    END
  END Tile_X1Y0_FrameData_O[29]
  PIN Tile_X1Y0_FrameData_O[2]
    DIRECTION OUTPUT ;
    USE SIGNAL ;
    ANTENNADIFFAREA 2.724000 ;
    PORT
      LAYER Metal3 ;
        RECT 431.600 17.020 432.000 17.420 ;
    END
  END Tile_X1Y0_FrameData_O[2]
  PIN Tile_X1Y0_FrameData_O[30]
    DIRECTION OUTPUT ;
    USE SIGNAL ;
    ANTENNADIFFAREA 2.724000 ;
    PORT
      LAYER Metal3 ;
        RECT 431.600 40.540 432.000 40.940 ;
    END
  END Tile_X1Y0_FrameData_O[30]
  PIN Tile_X1Y0_FrameData_O[31]
    DIRECTION OUTPUT ;
    USE SIGNAL ;
    ANTENNADIFFAREA 2.724000 ;
    PORT
      LAYER Metal3 ;
        RECT 431.600 41.380 432.000 41.780 ;
    END
  END Tile_X1Y0_FrameData_O[31]
  PIN Tile_X1Y0_FrameData_O[3]
    DIRECTION OUTPUT ;
    USE SIGNAL ;
    ANTENNADIFFAREA 2.724000 ;
    PORT
      LAYER Metal3 ;
        RECT 431.600 17.860 432.000 18.260 ;
    END
  END Tile_X1Y0_FrameData_O[3]
  PIN Tile_X1Y0_FrameData_O[4]
    DIRECTION OUTPUT ;
    USE SIGNAL ;
    ANTENNADIFFAREA 2.724000 ;
    PORT
      LAYER Metal3 ;
        RECT 431.600 18.700 432.000 19.100 ;
    END
  END Tile_X1Y0_FrameData_O[4]
  PIN Tile_X1Y0_FrameData_O[5]
    DIRECTION OUTPUT ;
    USE SIGNAL ;
    ANTENNADIFFAREA 2.724000 ;
    PORT
      LAYER Metal3 ;
        RECT 431.600 19.540 432.000 19.940 ;
    END
  END Tile_X1Y0_FrameData_O[5]
  PIN Tile_X1Y0_FrameData_O[6]
    DIRECTION OUTPUT ;
    USE SIGNAL ;
    ANTENNADIFFAREA 2.724000 ;
    PORT
      LAYER Metal3 ;
        RECT 431.600 20.380 432.000 20.780 ;
    END
  END Tile_X1Y0_FrameData_O[6]
  PIN Tile_X1Y0_FrameData_O[7]
    DIRECTION OUTPUT ;
    USE SIGNAL ;
    ANTENNADIFFAREA 2.724000 ;
    PORT
      LAYER Metal3 ;
        RECT 431.600 21.220 432.000 21.620 ;
    END
  END Tile_X1Y0_FrameData_O[7]
  PIN Tile_X1Y0_FrameData_O[8]
    DIRECTION OUTPUT ;
    USE SIGNAL ;
    ANTENNADIFFAREA 2.724000 ;
    PORT
      LAYER Metal3 ;
        RECT 431.600 22.060 432.000 22.460 ;
    END
  END Tile_X1Y0_FrameData_O[8]
  PIN Tile_X1Y0_FrameData_O[9]
    DIRECTION OUTPUT ;
    USE SIGNAL ;
    ANTENNADIFFAREA 2.724000 ;
    PORT
      LAYER Metal3 ;
        RECT 431.600 22.900 432.000 23.300 ;
    END
  END Tile_X1Y0_FrameData_O[9]
  PIN Tile_X1Y0_FrameStrobe[0]
    DIRECTION INPUT ;
    USE SIGNAL ;
    ANTENNAGATEAREA 0.180700 ;
    ANTENNADIFFAREA 2.015400 ;
    PORT
      LAYER Metal2 ;
        RECT 405.400 0.000 405.800 0.400 ;
    END
  END Tile_X1Y0_FrameStrobe[0]
  PIN Tile_X1Y0_FrameStrobe[10]
    DIRECTION INPUT ;
    USE SIGNAL ;
    ANTENNAGATEAREA 0.180700 ;
    ANTENNADIFFAREA 2.015400 ;
    PORT
      LAYER Metal2 ;
        RECT 415.000 0.000 415.400 0.400 ;
    END
  END Tile_X1Y0_FrameStrobe[10]
  PIN Tile_X1Y0_FrameStrobe[11]
    DIRECTION INPUT ;
    USE SIGNAL ;
    ANTENNAGATEAREA 0.180700 ;
    ANTENNADIFFAREA 2.015400 ;
    PORT
      LAYER Metal2 ;
        RECT 415.960 0.000 416.360 0.400 ;
    END
  END Tile_X1Y0_FrameStrobe[11]
  PIN Tile_X1Y0_FrameStrobe[12]
    DIRECTION INPUT ;
    USE SIGNAL ;
    ANTENNAGATEAREA 0.180700 ;
    ANTENNADIFFAREA 2.015400 ;
    PORT
      LAYER Metal2 ;
        RECT 416.920 0.000 417.320 0.400 ;
    END
  END Tile_X1Y0_FrameStrobe[12]
  PIN Tile_X1Y0_FrameStrobe[13]
    DIRECTION INPUT ;
    USE SIGNAL ;
    ANTENNAGATEAREA 0.180700 ;
    ANTENNADIFFAREA 2.015400 ;
    PORT
      LAYER Metal2 ;
        RECT 417.880 0.000 418.280 0.400 ;
    END
  END Tile_X1Y0_FrameStrobe[13]
  PIN Tile_X1Y0_FrameStrobe[14]
    DIRECTION INPUT ;
    USE SIGNAL ;
    ANTENNAGATEAREA 0.180700 ;
    ANTENNADIFFAREA 2.015400 ;
    PORT
      LAYER Metal2 ;
        RECT 418.840 0.000 419.240 0.400 ;
    END
  END Tile_X1Y0_FrameStrobe[14]
  PIN Tile_X1Y0_FrameStrobe[15]
    DIRECTION INPUT ;
    USE SIGNAL ;
    ANTENNAGATEAREA 0.180700 ;
    ANTENNADIFFAREA 2.015400 ;
    PORT
      LAYER Metal2 ;
        RECT 419.800 0.000 420.200 0.400 ;
    END
  END Tile_X1Y0_FrameStrobe[15]
  PIN Tile_X1Y0_FrameStrobe[16]
    DIRECTION INPUT ;
    USE SIGNAL ;
    ANTENNAGATEAREA 0.180700 ;
    ANTENNADIFFAREA 2.015400 ;
    PORT
      LAYER Metal2 ;
        RECT 420.760 0.000 421.160 0.400 ;
    END
  END Tile_X1Y0_FrameStrobe[16]
  PIN Tile_X1Y0_FrameStrobe[17]
    DIRECTION INPUT ;
    USE SIGNAL ;
    ANTENNAGATEAREA 0.180700 ;
    ANTENNADIFFAREA 2.015400 ;
    PORT
      LAYER Metal2 ;
        RECT 421.720 0.000 422.120 0.400 ;
    END
  END Tile_X1Y0_FrameStrobe[17]
  PIN Tile_X1Y0_FrameStrobe[18]
    DIRECTION INPUT ;
    USE SIGNAL ;
    ANTENNAGATEAREA 0.180700 ;
    ANTENNADIFFAREA 2.015400 ;
    PORT
      LAYER Metal2 ;
        RECT 422.680 0.000 423.080 0.400 ;
    END
  END Tile_X1Y0_FrameStrobe[18]
  PIN Tile_X1Y0_FrameStrobe[19]
    DIRECTION INPUT ;
    USE SIGNAL ;
    ANTENNAGATEAREA 0.180700 ;
    ANTENNADIFFAREA 2.015400 ;
    PORT
      LAYER Metal2 ;
        RECT 423.640 0.000 424.040 0.400 ;
    END
  END Tile_X1Y0_FrameStrobe[19]
  PIN Tile_X1Y0_FrameStrobe[1]
    DIRECTION INPUT ;
    USE SIGNAL ;
    ANTENNAGATEAREA 0.180700 ;
    ANTENNADIFFAREA 2.015400 ;
    PORT
      LAYER Metal2 ;
        RECT 406.360 0.000 406.760 0.400 ;
    END
  END Tile_X1Y0_FrameStrobe[1]
  PIN Tile_X1Y0_FrameStrobe[2]
    DIRECTION INPUT ;
    USE SIGNAL ;
    ANTENNAGATEAREA 0.180700 ;
    ANTENNADIFFAREA 2.015400 ;
    PORT
      LAYER Metal2 ;
        RECT 407.320 0.000 407.720 0.400 ;
    END
  END Tile_X1Y0_FrameStrobe[2]
  PIN Tile_X1Y0_FrameStrobe[3]
    DIRECTION INPUT ;
    USE SIGNAL ;
    ANTENNAGATEAREA 0.180700 ;
    ANTENNADIFFAREA 2.015400 ;
    PORT
      LAYER Metal2 ;
        RECT 408.280 0.000 408.680 0.400 ;
    END
  END Tile_X1Y0_FrameStrobe[3]
  PIN Tile_X1Y0_FrameStrobe[4]
    DIRECTION INPUT ;
    USE SIGNAL ;
    ANTENNAGATEAREA 0.180700 ;
    ANTENNADIFFAREA 2.015400 ;
    PORT
      LAYER Metal2 ;
        RECT 409.240 0.000 409.640 0.400 ;
    END
  END Tile_X1Y0_FrameStrobe[4]
  PIN Tile_X1Y0_FrameStrobe[5]
    DIRECTION INPUT ;
    USE SIGNAL ;
    ANTENNAGATEAREA 0.180700 ;
    ANTENNADIFFAREA 2.015400 ;
    PORT
      LAYER Metal2 ;
        RECT 410.200 0.000 410.600 0.400 ;
    END
  END Tile_X1Y0_FrameStrobe[5]
  PIN Tile_X1Y0_FrameStrobe[6]
    DIRECTION INPUT ;
    USE SIGNAL ;
    ANTENNAGATEAREA 0.180700 ;
    ANTENNADIFFAREA 2.015400 ;
    PORT
      LAYER Metal2 ;
        RECT 411.160 0.000 411.560 0.400 ;
    END
  END Tile_X1Y0_FrameStrobe[6]
  PIN Tile_X1Y0_FrameStrobe[7]
    DIRECTION INPUT ;
    USE SIGNAL ;
    ANTENNAGATEAREA 0.180700 ;
    ANTENNADIFFAREA 2.015400 ;
    PORT
      LAYER Metal2 ;
        RECT 412.120 0.000 412.520 0.400 ;
    END
  END Tile_X1Y0_FrameStrobe[7]
  PIN Tile_X1Y0_FrameStrobe[8]
    DIRECTION INPUT ;
    USE SIGNAL ;
    ANTENNAGATEAREA 0.180700 ;
    ANTENNADIFFAREA 2.015400 ;
    PORT
      LAYER Metal2 ;
        RECT 413.080 0.000 413.480 0.400 ;
    END
  END Tile_X1Y0_FrameStrobe[8]
  PIN Tile_X1Y0_FrameStrobe[9]
    DIRECTION INPUT ;
    USE SIGNAL ;
    ANTENNAGATEAREA 0.180700 ;
    ANTENNADIFFAREA 2.015400 ;
    PORT
      LAYER Metal2 ;
        RECT 414.040 0.000 414.440 0.400 ;
    END
  END Tile_X1Y0_FrameStrobe[9]
  PIN Tile_X1Y0_FrameStrobe_O[0]
    DIRECTION OUTPUT ;
    USE SIGNAL ;
    ANTENNADIFFAREA 2.724000 ;
    PORT
      LAYER Metal2 ;
        RECT 219.160 54.200 219.560 54.600 ;
    END
  END Tile_X1Y0_FrameStrobe_O[0]
  PIN Tile_X1Y0_FrameStrobe_O[10]
    DIRECTION OUTPUT ;
    USE SIGNAL ;
    ANTENNADIFFAREA 2.724000 ;
    PORT
      LAYER Metal2 ;
        RECT 238.360 54.200 238.760 54.600 ;
    END
  END Tile_X1Y0_FrameStrobe_O[10]
  PIN Tile_X1Y0_FrameStrobe_O[11]
    DIRECTION OUTPUT ;
    USE SIGNAL ;
    ANTENNADIFFAREA 2.724000 ;
    PORT
      LAYER Metal2 ;
        RECT 240.280 54.200 240.680 54.600 ;
    END
  END Tile_X1Y0_FrameStrobe_O[11]
  PIN Tile_X1Y0_FrameStrobe_O[12]
    DIRECTION OUTPUT ;
    USE SIGNAL ;
    ANTENNADIFFAREA 2.724000 ;
    PORT
      LAYER Metal2 ;
        RECT 242.200 54.200 242.600 54.600 ;
    END
  END Tile_X1Y0_FrameStrobe_O[12]
  PIN Tile_X1Y0_FrameStrobe_O[13]
    DIRECTION OUTPUT ;
    USE SIGNAL ;
    ANTENNADIFFAREA 2.724000 ;
    PORT
      LAYER Metal2 ;
        RECT 244.120 54.200 244.520 54.600 ;
    END
  END Tile_X1Y0_FrameStrobe_O[13]
  PIN Tile_X1Y0_FrameStrobe_O[14]
    DIRECTION OUTPUT ;
    USE SIGNAL ;
    ANTENNADIFFAREA 2.724000 ;
    PORT
      LAYER Metal2 ;
        RECT 246.040 54.200 246.440 54.600 ;
    END
  END Tile_X1Y0_FrameStrobe_O[14]
  PIN Tile_X1Y0_FrameStrobe_O[15]
    DIRECTION OUTPUT ;
    USE SIGNAL ;
    ANTENNADIFFAREA 2.724000 ;
    PORT
      LAYER Metal2 ;
        RECT 247.960 54.200 248.360 54.600 ;
    END
  END Tile_X1Y0_FrameStrobe_O[15]
  PIN Tile_X1Y0_FrameStrobe_O[16]
    DIRECTION OUTPUT ;
    USE SIGNAL ;
    ANTENNADIFFAREA 2.724000 ;
    PORT
      LAYER Metal2 ;
        RECT 249.880 54.200 250.280 54.600 ;
    END
  END Tile_X1Y0_FrameStrobe_O[16]
  PIN Tile_X1Y0_FrameStrobe_O[17]
    DIRECTION OUTPUT ;
    USE SIGNAL ;
    ANTENNADIFFAREA 2.724000 ;
    PORT
      LAYER Metal2 ;
        RECT 251.800 54.200 252.200 54.600 ;
    END
  END Tile_X1Y0_FrameStrobe_O[17]
  PIN Tile_X1Y0_FrameStrobe_O[18]
    DIRECTION OUTPUT ;
    USE SIGNAL ;
    ANTENNADIFFAREA 2.724000 ;
    PORT
      LAYER Metal2 ;
        RECT 253.720 54.200 254.120 54.600 ;
    END
  END Tile_X1Y0_FrameStrobe_O[18]
  PIN Tile_X1Y0_FrameStrobe_O[19]
    DIRECTION OUTPUT ;
    USE SIGNAL ;
    ANTENNADIFFAREA 2.724000 ;
    PORT
      LAYER Metal2 ;
        RECT 255.640 54.200 256.040 54.600 ;
    END
  END Tile_X1Y0_FrameStrobe_O[19]
  PIN Tile_X1Y0_FrameStrobe_O[1]
    DIRECTION OUTPUT ;
    USE SIGNAL ;
    ANTENNADIFFAREA 2.724000 ;
    PORT
      LAYER Metal2 ;
        RECT 221.080 54.200 221.480 54.600 ;
    END
  END Tile_X1Y0_FrameStrobe_O[1]
  PIN Tile_X1Y0_FrameStrobe_O[2]
    DIRECTION OUTPUT ;
    USE SIGNAL ;
    ANTENNADIFFAREA 2.724000 ;
    PORT
      LAYER Metal2 ;
        RECT 223.000 54.200 223.400 54.600 ;
    END
  END Tile_X1Y0_FrameStrobe_O[2]
  PIN Tile_X1Y0_FrameStrobe_O[3]
    DIRECTION OUTPUT ;
    USE SIGNAL ;
    ANTENNADIFFAREA 2.724000 ;
    PORT
      LAYER Metal2 ;
        RECT 224.920 54.200 225.320 54.600 ;
    END
  END Tile_X1Y0_FrameStrobe_O[3]
  PIN Tile_X1Y0_FrameStrobe_O[4]
    DIRECTION OUTPUT ;
    USE SIGNAL ;
    ANTENNADIFFAREA 2.724000 ;
    PORT
      LAYER Metal2 ;
        RECT 226.840 54.200 227.240 54.600 ;
    END
  END Tile_X1Y0_FrameStrobe_O[4]
  PIN Tile_X1Y0_FrameStrobe_O[5]
    DIRECTION OUTPUT ;
    USE SIGNAL ;
    ANTENNADIFFAREA 2.724000 ;
    PORT
      LAYER Metal2 ;
        RECT 228.760 54.200 229.160 54.600 ;
    END
  END Tile_X1Y0_FrameStrobe_O[5]
  PIN Tile_X1Y0_FrameStrobe_O[6]
    DIRECTION OUTPUT ;
    USE SIGNAL ;
    ANTENNADIFFAREA 2.724000 ;
    PORT
      LAYER Metal2 ;
        RECT 230.680 54.200 231.080 54.600 ;
    END
  END Tile_X1Y0_FrameStrobe_O[6]
  PIN Tile_X1Y0_FrameStrobe_O[7]
    DIRECTION OUTPUT ;
    USE SIGNAL ;
    ANTENNADIFFAREA 2.724000 ;
    PORT
      LAYER Metal2 ;
        RECT 232.600 54.200 233.000 54.600 ;
    END
  END Tile_X1Y0_FrameStrobe_O[7]
  PIN Tile_X1Y0_FrameStrobe_O[8]
    DIRECTION OUTPUT ;
    USE SIGNAL ;
    ANTENNADIFFAREA 2.724000 ;
    PORT
      LAYER Metal2 ;
        RECT 234.520 54.200 234.920 54.600 ;
    END
  END Tile_X1Y0_FrameStrobe_O[8]
  PIN Tile_X1Y0_FrameStrobe_O[9]
    DIRECTION OUTPUT ;
    USE SIGNAL ;
    ANTENNADIFFAREA 2.724000 ;
    PORT
      LAYER Metal2 ;
        RECT 236.440 54.200 236.840 54.600 ;
    END
  END Tile_X1Y0_FrameStrobe_O[9]
  PIN Tile_X1Y0_N1END[0]
    DIRECTION INPUT ;
    USE SIGNAL ;
    ANTENNAGATEAREA 0.180700 ;
    ANTENNADIFFAREA 2.015400 ;
    PORT
      LAYER Metal2 ;
        RECT 218.200 0.000 218.600 0.400 ;
    END
  END Tile_X1Y0_N1END[0]
  PIN Tile_X1Y0_N1END[1]
    DIRECTION INPUT ;
    USE SIGNAL ;
    ANTENNAGATEAREA 0.180700 ;
    ANTENNADIFFAREA 2.015400 ;
    PORT
      LAYER Metal2 ;
        RECT 219.160 0.000 219.560 0.400 ;
    END
  END Tile_X1Y0_N1END[1]
  PIN Tile_X1Y0_N1END[2]
    DIRECTION INPUT ;
    USE SIGNAL ;
    ANTENNAGATEAREA 0.180700 ;
    ANTENNADIFFAREA 2.015400 ;
    PORT
      LAYER Metal2 ;
        RECT 220.120 0.000 220.520 0.400 ;
    END
  END Tile_X1Y0_N1END[2]
  PIN Tile_X1Y0_N1END[3]
    DIRECTION INPUT ;
    USE SIGNAL ;
    ANTENNAGATEAREA 0.180700 ;
    ANTENNADIFFAREA 2.015400 ;
    PORT
      LAYER Metal2 ;
        RECT 221.080 0.000 221.480 0.400 ;
    END
  END Tile_X1Y0_N1END[3]
  PIN Tile_X1Y0_N2END[0]
    DIRECTION INPUT ;
    USE SIGNAL ;
    ANTENNAGATEAREA 0.180700 ;
    ANTENNADIFFAREA 2.015400 ;
    PORT
      LAYER Metal2 ;
        RECT 240.280 0.000 240.680 0.400 ;
    END
  END Tile_X1Y0_N2END[0]
  PIN Tile_X1Y0_N2END[1]
    DIRECTION INPUT ;
    USE SIGNAL ;
    ANTENNAGATEAREA 0.180700 ;
    ANTENNADIFFAREA 2.015400 ;
    PORT
      LAYER Metal2 ;
        RECT 241.240 0.000 241.640 0.400 ;
    END
  END Tile_X1Y0_N2END[1]
  PIN Tile_X1Y0_N2END[2]
    DIRECTION INPUT ;
    USE SIGNAL ;
    ANTENNAGATEAREA 0.180700 ;
    ANTENNADIFFAREA 2.015400 ;
    PORT
      LAYER Metal2 ;
        RECT 242.200 0.000 242.600 0.400 ;
    END
  END Tile_X1Y0_N2END[2]
  PIN Tile_X1Y0_N2END[3]
    DIRECTION INPUT ;
    USE SIGNAL ;
    ANTENNAGATEAREA 0.180700 ;
    ANTENNADIFFAREA 2.015400 ;
    PORT
      LAYER Metal2 ;
        RECT 243.160 0.000 243.560 0.400 ;
    END
  END Tile_X1Y0_N2END[3]
  PIN Tile_X1Y0_N2END[4]
    DIRECTION INPUT ;
    USE SIGNAL ;
    ANTENNAGATEAREA 0.180700 ;
    ANTENNADIFFAREA 2.015400 ;
    PORT
      LAYER Metal2 ;
        RECT 244.120 0.000 244.520 0.400 ;
    END
  END Tile_X1Y0_N2END[4]
  PIN Tile_X1Y0_N2END[5]
    DIRECTION INPUT ;
    USE SIGNAL ;
    ANTENNAGATEAREA 0.180700 ;
    ANTENNADIFFAREA 2.015400 ;
    PORT
      LAYER Metal2 ;
        RECT 245.080 0.000 245.480 0.400 ;
    END
  END Tile_X1Y0_N2END[5]
  PIN Tile_X1Y0_N2END[6]
    DIRECTION INPUT ;
    USE SIGNAL ;
    ANTENNAGATEAREA 0.180700 ;
    ANTENNADIFFAREA 2.015400 ;
    PORT
      LAYER Metal2 ;
        RECT 246.040 0.000 246.440 0.400 ;
    END
  END Tile_X1Y0_N2END[6]
  PIN Tile_X1Y0_N2END[7]
    DIRECTION INPUT ;
    USE SIGNAL ;
    ANTENNAGATEAREA 0.180700 ;
    ANTENNADIFFAREA 2.015400 ;
    PORT
      LAYER Metal2 ;
        RECT 247.000 0.000 247.400 0.400 ;
    END
  END Tile_X1Y0_N2END[7]
  PIN Tile_X1Y0_N2MID[0]
    DIRECTION INPUT ;
    USE SIGNAL ;
    ANTENNAGATEAREA 0.180700 ;
    ANTENNADIFFAREA 2.015400 ;
    PORT
      LAYER Metal2 ;
        RECT 226.840 0.000 227.240 0.400 ;
    END
  END Tile_X1Y0_N2MID[0]
  PIN Tile_X1Y0_N2MID[1]
    DIRECTION INPUT ;
    USE SIGNAL ;
    ANTENNAGATEAREA 0.180700 ;
    ANTENNADIFFAREA 2.015400 ;
    PORT
      LAYER Metal2 ;
        RECT 227.800 0.000 228.200 0.400 ;
    END
  END Tile_X1Y0_N2MID[1]
  PIN Tile_X1Y0_N2MID[2]
    DIRECTION INPUT ;
    USE SIGNAL ;
    ANTENNAGATEAREA 0.180700 ;
    ANTENNADIFFAREA 2.015400 ;
    PORT
      LAYER Metal2 ;
        RECT 228.760 0.000 229.160 0.400 ;
    END
  END Tile_X1Y0_N2MID[2]
  PIN Tile_X1Y0_N2MID[3]
    DIRECTION INPUT ;
    USE SIGNAL ;
    ANTENNAGATEAREA 0.180700 ;
    ANTENNADIFFAREA 2.015400 ;
    PORT
      LAYER Metal2 ;
        RECT 229.720 0.000 230.120 0.400 ;
    END
  END Tile_X1Y0_N2MID[3]
  PIN Tile_X1Y0_N2MID[4]
    DIRECTION INPUT ;
    USE SIGNAL ;
    ANTENNAGATEAREA 0.180700 ;
    ANTENNADIFFAREA 2.015400 ;
    PORT
      LAYER Metal2 ;
        RECT 230.680 0.000 231.080 0.400 ;
    END
  END Tile_X1Y0_N2MID[4]
  PIN Tile_X1Y0_N2MID[5]
    DIRECTION INPUT ;
    USE SIGNAL ;
    ANTENNAGATEAREA 0.180700 ;
    ANTENNADIFFAREA 2.015400 ;
    PORT
      LAYER Metal2 ;
        RECT 231.640 0.000 232.040 0.400 ;
    END
  END Tile_X1Y0_N2MID[5]
  PIN Tile_X1Y0_N2MID[6]
    DIRECTION INPUT ;
    USE SIGNAL ;
    ANTENNAGATEAREA 0.180700 ;
    ANTENNADIFFAREA 2.015400 ;
    PORT
      LAYER Metal2 ;
        RECT 232.600 0.000 233.000 0.400 ;
    END
  END Tile_X1Y0_N2MID[6]
  PIN Tile_X1Y0_N2MID[7]
    DIRECTION INPUT ;
    USE SIGNAL ;
    ANTENNAGATEAREA 0.180700 ;
    ANTENNADIFFAREA 2.015400 ;
    PORT
      LAYER Metal2 ;
        RECT 233.560 0.000 233.960 0.400 ;
    END
  END Tile_X1Y0_N2MID[7]
  PIN Tile_X1Y0_N4END[0]
    DIRECTION INPUT ;
    USE SIGNAL ;
    ANTENNAGATEAREA 0.180700 ;
    ANTENNADIFFAREA 2.015400 ;
    PORT
      LAYER Metal2 ;
        RECT 256.600 0.000 257.000 0.400 ;
    END
  END Tile_X1Y0_N4END[0]
  PIN Tile_X1Y0_N4END[10]
    DIRECTION INPUT ;
    USE SIGNAL ;
    ANTENNAGATEAREA 0.180700 ;
    ANTENNADIFFAREA 2.015400 ;
    PORT
      LAYER Metal2 ;
        RECT 266.200 0.000 266.600 0.400 ;
    END
  END Tile_X1Y0_N4END[10]
  PIN Tile_X1Y0_N4END[11]
    DIRECTION INPUT ;
    USE SIGNAL ;
    ANTENNAGATEAREA 0.180700 ;
    ANTENNADIFFAREA 2.015400 ;
    PORT
      LAYER Metal2 ;
        RECT 267.160 0.000 267.560 0.400 ;
    END
  END Tile_X1Y0_N4END[11]
  PIN Tile_X1Y0_N4END[12]
    DIRECTION INPUT ;
    USE SIGNAL ;
    ANTENNAGATEAREA 0.180700 ;
    ANTENNADIFFAREA 2.015400 ;
    PORT
      LAYER Metal2 ;
        RECT 268.120 0.000 268.520 0.400 ;
    END
  END Tile_X1Y0_N4END[12]
  PIN Tile_X1Y0_N4END[13]
    DIRECTION INPUT ;
    USE SIGNAL ;
    ANTENNAGATEAREA 0.180700 ;
    ANTENNADIFFAREA 2.015400 ;
    PORT
      LAYER Metal2 ;
        RECT 269.080 0.000 269.480 0.400 ;
    END
  END Tile_X1Y0_N4END[13]
  PIN Tile_X1Y0_N4END[14]
    DIRECTION INPUT ;
    USE SIGNAL ;
    ANTENNAGATEAREA 0.180700 ;
    ANTENNADIFFAREA 2.015400 ;
    PORT
      LAYER Metal2 ;
        RECT 270.040 0.000 270.440 0.400 ;
    END
  END Tile_X1Y0_N4END[14]
  PIN Tile_X1Y0_N4END[15]
    DIRECTION INPUT ;
    USE SIGNAL ;
    ANTENNAGATEAREA 0.180700 ;
    ANTENNADIFFAREA 2.015400 ;
    PORT
      LAYER Metal2 ;
        RECT 271.000 0.000 271.400 0.400 ;
    END
  END Tile_X1Y0_N4END[15]
  PIN Tile_X1Y0_N4END[1]
    DIRECTION INPUT ;
    USE SIGNAL ;
    ANTENNAGATEAREA 0.180700 ;
    ANTENNADIFFAREA 2.015400 ;
    PORT
      LAYER Metal2 ;
        RECT 257.560 0.000 257.960 0.400 ;
    END
  END Tile_X1Y0_N4END[1]
  PIN Tile_X1Y0_N4END[2]
    DIRECTION INPUT ;
    USE SIGNAL ;
    ANTENNAGATEAREA 0.180700 ;
    ANTENNADIFFAREA 2.015400 ;
    PORT
      LAYER Metal2 ;
        RECT 258.520 0.000 258.920 0.400 ;
    END
  END Tile_X1Y0_N4END[2]
  PIN Tile_X1Y0_N4END[3]
    DIRECTION INPUT ;
    USE SIGNAL ;
    ANTENNAGATEAREA 0.180700 ;
    ANTENNADIFFAREA 2.015400 ;
    PORT
      LAYER Metal2 ;
        RECT 259.480 0.000 259.880 0.400 ;
    END
  END Tile_X1Y0_N4END[3]
  PIN Tile_X1Y0_N4END[4]
    DIRECTION INPUT ;
    USE SIGNAL ;
    ANTENNAGATEAREA 0.180700 ;
    ANTENNADIFFAREA 2.015400 ;
    PORT
      LAYER Metal2 ;
        RECT 260.440 0.000 260.840 0.400 ;
    END
  END Tile_X1Y0_N4END[4]
  PIN Tile_X1Y0_N4END[5]
    DIRECTION INPUT ;
    USE SIGNAL ;
    ANTENNAGATEAREA 0.180700 ;
    ANTENNADIFFAREA 2.015400 ;
    PORT
      LAYER Metal2 ;
        RECT 261.400 0.000 261.800 0.400 ;
    END
  END Tile_X1Y0_N4END[5]
  PIN Tile_X1Y0_N4END[6]
    DIRECTION INPUT ;
    USE SIGNAL ;
    ANTENNAGATEAREA 0.180700 ;
    ANTENNADIFFAREA 2.015400 ;
    PORT
      LAYER Metal2 ;
        RECT 262.360 0.000 262.760 0.400 ;
    END
  END Tile_X1Y0_N4END[6]
  PIN Tile_X1Y0_N4END[7]
    DIRECTION INPUT ;
    USE SIGNAL ;
    ANTENNAGATEAREA 0.180700 ;
    ANTENNADIFFAREA 2.015400 ;
    PORT
      LAYER Metal2 ;
        RECT 263.320 0.000 263.720 0.400 ;
    END
  END Tile_X1Y0_N4END[7]
  PIN Tile_X1Y0_N4END[8]
    DIRECTION INPUT ;
    USE SIGNAL ;
    ANTENNAGATEAREA 0.180700 ;
    ANTENNADIFFAREA 2.015400 ;
    PORT
      LAYER Metal2 ;
        RECT 264.280 0.000 264.680 0.400 ;
    END
  END Tile_X1Y0_N4END[8]
  PIN Tile_X1Y0_N4END[9]
    DIRECTION INPUT ;
    USE SIGNAL ;
    ANTENNAGATEAREA 0.180700 ;
    ANTENNADIFFAREA 2.015400 ;
    PORT
      LAYER Metal2 ;
        RECT 265.240 0.000 265.640 0.400 ;
    END
  END Tile_X1Y0_N4END[9]
  PIN Tile_X1Y0_NN4END[0]
    DIRECTION INPUT ;
    USE SIGNAL ;
    ANTENNAGATEAREA 0.180700 ;
    ANTENNADIFFAREA 2.015400 ;
    PORT
      LAYER Metal2 ;
        RECT 284.440 0.000 284.840 0.400 ;
    END
  END Tile_X1Y0_NN4END[0]
  PIN Tile_X1Y0_NN4END[10]
    DIRECTION INPUT ;
    USE SIGNAL ;
    ANTENNAGATEAREA 0.180700 ;
    ANTENNADIFFAREA 2.015400 ;
    PORT
      LAYER Metal2 ;
        RECT 294.040 0.000 294.440 0.400 ;
    END
  END Tile_X1Y0_NN4END[10]
  PIN Tile_X1Y0_NN4END[11]
    DIRECTION INPUT ;
    USE SIGNAL ;
    ANTENNAGATEAREA 0.180700 ;
    ANTENNADIFFAREA 2.015400 ;
    PORT
      LAYER Metal2 ;
        RECT 295.000 0.000 295.400 0.400 ;
    END
  END Tile_X1Y0_NN4END[11]
  PIN Tile_X1Y0_NN4END[12]
    DIRECTION INPUT ;
    USE SIGNAL ;
    ANTENNAGATEAREA 0.180700 ;
    ANTENNADIFFAREA 2.015400 ;
    PORT
      LAYER Metal2 ;
        RECT 295.960 0.000 296.360 0.400 ;
    END
  END Tile_X1Y0_NN4END[12]
  PIN Tile_X1Y0_NN4END[13]
    DIRECTION INPUT ;
    USE SIGNAL ;
    ANTENNAGATEAREA 0.361400 ;
    ANTENNADIFFAREA 4.030800 ;
    PORT
      LAYER Metal2 ;
        RECT 296.920 0.000 297.320 0.400 ;
    END
  END Tile_X1Y0_NN4END[13]
  PIN Tile_X1Y0_NN4END[14]
    DIRECTION INPUT ;
    USE SIGNAL ;
    ANTENNAGATEAREA 0.361400 ;
    ANTENNADIFFAREA 4.030800 ;
    PORT
      LAYER Metal2 ;
        RECT 297.880 0.000 298.280 0.400 ;
    END
  END Tile_X1Y0_NN4END[14]
  PIN Tile_X1Y0_NN4END[15]
    DIRECTION INPUT ;
    USE SIGNAL ;
    ANTENNAGATEAREA 0.361400 ;
    ANTENNADIFFAREA 4.030800 ;
    PORT
      LAYER Metal2 ;
        RECT 298.840 0.000 299.240 0.400 ;
    END
  END Tile_X1Y0_NN4END[15]
  PIN Tile_X1Y0_NN4END[1]
    DIRECTION INPUT ;
    USE SIGNAL ;
    ANTENNAGATEAREA 0.180700 ;
    ANTENNADIFFAREA 2.015400 ;
    PORT
      LAYER Metal2 ;
        RECT 285.400 0.000 285.800 0.400 ;
    END
  END Tile_X1Y0_NN4END[1]
  PIN Tile_X1Y0_NN4END[2]
    DIRECTION INPUT ;
    USE SIGNAL ;
    ANTENNAGATEAREA 0.180700 ;
    ANTENNADIFFAREA 2.015400 ;
    PORT
      LAYER Metal2 ;
        RECT 286.360 0.000 286.760 0.400 ;
    END
  END Tile_X1Y0_NN4END[2]
  PIN Tile_X1Y0_NN4END[3]
    DIRECTION INPUT ;
    USE SIGNAL ;
    ANTENNAGATEAREA 0.180700 ;
    ANTENNADIFFAREA 2.015400 ;
    PORT
      LAYER Metal2 ;
        RECT 287.320 0.000 287.720 0.400 ;
    END
  END Tile_X1Y0_NN4END[3]
  PIN Tile_X1Y0_NN4END[4]
    DIRECTION INPUT ;
    USE SIGNAL ;
    ANTENNAGATEAREA 0.180700 ;
    ANTENNADIFFAREA 2.015400 ;
    PORT
      LAYER Metal2 ;
        RECT 288.280 0.000 288.680 0.400 ;
    END
  END Tile_X1Y0_NN4END[4]
  PIN Tile_X1Y0_NN4END[5]
    DIRECTION INPUT ;
    USE SIGNAL ;
    ANTENNAGATEAREA 0.180700 ;
    ANTENNADIFFAREA 2.015400 ;
    PORT
      LAYER Metal2 ;
        RECT 289.240 0.000 289.640 0.400 ;
    END
  END Tile_X1Y0_NN4END[5]
  PIN Tile_X1Y0_NN4END[6]
    DIRECTION INPUT ;
    USE SIGNAL ;
    ANTENNAGATEAREA 0.180700 ;
    ANTENNADIFFAREA 2.015400 ;
    PORT
      LAYER Metal2 ;
        RECT 290.200 0.000 290.600 0.400 ;
    END
  END Tile_X1Y0_NN4END[6]
  PIN Tile_X1Y0_NN4END[7]
    DIRECTION INPUT ;
    USE SIGNAL ;
    ANTENNAGATEAREA 0.180700 ;
    ANTENNADIFFAREA 2.015400 ;
    PORT
      LAYER Metal2 ;
        RECT 291.160 0.000 291.560 0.400 ;
    END
  END Tile_X1Y0_NN4END[7]
  PIN Tile_X1Y0_NN4END[8]
    DIRECTION INPUT ;
    USE SIGNAL ;
    ANTENNAGATEAREA 0.180700 ;
    ANTENNADIFFAREA 2.015400 ;
    PORT
      LAYER Metal2 ;
        RECT 292.120 0.000 292.520 0.400 ;
    END
  END Tile_X1Y0_NN4END[8]
  PIN Tile_X1Y0_NN4END[9]
    DIRECTION INPUT ;
    USE SIGNAL ;
    ANTENNAGATEAREA 0.180700 ;
    ANTENNADIFFAREA 2.015400 ;
    PORT
      LAYER Metal2 ;
        RECT 293.080 0.000 293.480 0.400 ;
    END
  END Tile_X1Y0_NN4END[9]
  PIN Tile_X1Y0_S1BEG[0]
    DIRECTION OUTPUT ;
    USE SIGNAL ;
    ANTENNADIFFAREA 2.724000 ;
    PORT
      LAYER Metal2 ;
        RECT 306.520 0.000 306.920 0.400 ;
    END
  END Tile_X1Y0_S1BEG[0]
  PIN Tile_X1Y0_S1BEG[1]
    DIRECTION OUTPUT ;
    USE SIGNAL ;
    ANTENNADIFFAREA 2.724000 ;
    PORT
      LAYER Metal2 ;
        RECT 307.480 0.000 307.880 0.400 ;
    END
  END Tile_X1Y0_S1BEG[1]
  PIN Tile_X1Y0_S1BEG[2]
    DIRECTION OUTPUT ;
    USE SIGNAL ;
    ANTENNADIFFAREA 2.724000 ;
    PORT
      LAYER Metal2 ;
        RECT 308.440 0.000 308.840 0.400 ;
    END
  END Tile_X1Y0_S1BEG[2]
  PIN Tile_X1Y0_S1BEG[3]
    DIRECTION OUTPUT ;
    USE SIGNAL ;
    ANTENNADIFFAREA 2.724000 ;
    PORT
      LAYER Metal2 ;
        RECT 309.400 0.000 309.800 0.400 ;
    END
  END Tile_X1Y0_S1BEG[3]
  PIN Tile_X1Y0_S2BEG[0]
    DIRECTION OUTPUT ;
    USE SIGNAL ;
    ANTENNADIFFAREA 2.724000 ;
    PORT
      LAYER Metal2 ;
        RECT 315.160 0.000 315.560 0.400 ;
    END
  END Tile_X1Y0_S2BEG[0]
  PIN Tile_X1Y0_S2BEG[1]
    DIRECTION OUTPUT ;
    USE SIGNAL ;
    ANTENNADIFFAREA 2.724000 ;
    PORT
      LAYER Metal2 ;
        RECT 316.120 0.000 316.520 0.400 ;
    END
  END Tile_X1Y0_S2BEG[1]
  PIN Tile_X1Y0_S2BEG[2]
    DIRECTION OUTPUT ;
    USE SIGNAL ;
    ANTENNADIFFAREA 2.724000 ;
    PORT
      LAYER Metal2 ;
        RECT 317.080 0.000 317.480 0.400 ;
    END
  END Tile_X1Y0_S2BEG[2]
  PIN Tile_X1Y0_S2BEG[3]
    DIRECTION OUTPUT ;
    USE SIGNAL ;
    ANTENNADIFFAREA 2.724000 ;
    PORT
      LAYER Metal2 ;
        RECT 318.040 0.000 318.440 0.400 ;
    END
  END Tile_X1Y0_S2BEG[3]
  PIN Tile_X1Y0_S2BEG[4]
    DIRECTION OUTPUT ;
    USE SIGNAL ;
    ANTENNADIFFAREA 2.724000 ;
    PORT
      LAYER Metal2 ;
        RECT 319.000 0.000 319.400 0.400 ;
    END
  END Tile_X1Y0_S2BEG[4]
  PIN Tile_X1Y0_S2BEG[5]
    DIRECTION OUTPUT ;
    USE SIGNAL ;
    ANTENNADIFFAREA 2.724000 ;
    PORT
      LAYER Metal2 ;
        RECT 319.960 0.000 320.360 0.400 ;
    END
  END Tile_X1Y0_S2BEG[5]
  PIN Tile_X1Y0_S2BEG[6]
    DIRECTION OUTPUT ;
    USE SIGNAL ;
    ANTENNADIFFAREA 2.724000 ;
    PORT
      LAYER Metal2 ;
        RECT 320.920 0.000 321.320 0.400 ;
    END
  END Tile_X1Y0_S2BEG[6]
  PIN Tile_X1Y0_S2BEG[7]
    DIRECTION OUTPUT ;
    USE SIGNAL ;
    ANTENNADIFFAREA 2.724000 ;
    PORT
      LAYER Metal2 ;
        RECT 321.880 0.000 322.280 0.400 ;
    END
  END Tile_X1Y0_S2BEG[7]
  PIN Tile_X1Y0_S2BEGb[0]
    DIRECTION OUTPUT ;
    USE SIGNAL ;
    ANTENNADIFFAREA 2.724000 ;
    PORT
      LAYER Metal2 ;
        RECT 329.560 0.000 329.960 0.400 ;
    END
  END Tile_X1Y0_S2BEGb[0]
  PIN Tile_X1Y0_S2BEGb[1]
    DIRECTION OUTPUT ;
    USE SIGNAL ;
    ANTENNADIFFAREA 2.724000 ;
    PORT
      LAYER Metal2 ;
        RECT 330.520 0.000 330.920 0.400 ;
    END
  END Tile_X1Y0_S2BEGb[1]
  PIN Tile_X1Y0_S2BEGb[2]
    DIRECTION OUTPUT ;
    USE SIGNAL ;
    ANTENNADIFFAREA 2.724000 ;
    PORT
      LAYER Metal2 ;
        RECT 331.480 0.000 331.880 0.400 ;
    END
  END Tile_X1Y0_S2BEGb[2]
  PIN Tile_X1Y0_S2BEGb[3]
    DIRECTION OUTPUT ;
    USE SIGNAL ;
    ANTENNADIFFAREA 2.724000 ;
    PORT
      LAYER Metal2 ;
        RECT 332.440 0.000 332.840 0.400 ;
    END
  END Tile_X1Y0_S2BEGb[3]
  PIN Tile_X1Y0_S2BEGb[4]
    DIRECTION OUTPUT ;
    USE SIGNAL ;
    ANTENNADIFFAREA 2.724000 ;
    PORT
      LAYER Metal2 ;
        RECT 333.400 0.000 333.800 0.400 ;
    END
  END Tile_X1Y0_S2BEGb[4]
  PIN Tile_X1Y0_S2BEGb[5]
    DIRECTION OUTPUT ;
    USE SIGNAL ;
    ANTENNADIFFAREA 2.724000 ;
    PORT
      LAYER Metal2 ;
        RECT 334.360 0.000 334.760 0.400 ;
    END
  END Tile_X1Y0_S2BEGb[5]
  PIN Tile_X1Y0_S2BEGb[6]
    DIRECTION OUTPUT ;
    USE SIGNAL ;
    ANTENNADIFFAREA 2.724000 ;
    PORT
      LAYER Metal2 ;
        RECT 335.320 0.000 335.720 0.400 ;
    END
  END Tile_X1Y0_S2BEGb[6]
  PIN Tile_X1Y0_S2BEGb[7]
    DIRECTION OUTPUT ;
    USE SIGNAL ;
    ANTENNADIFFAREA 2.724000 ;
    PORT
      LAYER Metal2 ;
        RECT 336.280 0.000 336.680 0.400 ;
    END
  END Tile_X1Y0_S2BEGb[7]
  PIN Tile_X1Y0_S4BEG[0]
    DIRECTION OUTPUT ;
    USE SIGNAL ;
    ANTENNADIFFAREA 2.724000 ;
    PORT
      LAYER Metal2 ;
        RECT 345.880 0.000 346.280 0.400 ;
    END
  END Tile_X1Y0_S4BEG[0]
  PIN Tile_X1Y0_S4BEG[10]
    DIRECTION OUTPUT ;
    USE SIGNAL ;
    ANTENNADIFFAREA 2.724000 ;
    PORT
      LAYER Metal2 ;
        RECT 355.480 0.000 355.880 0.400 ;
    END
  END Tile_X1Y0_S4BEG[10]
  PIN Tile_X1Y0_S4BEG[11]
    DIRECTION OUTPUT ;
    USE SIGNAL ;
    ANTENNADIFFAREA 2.724000 ;
    PORT
      LAYER Metal2 ;
        RECT 356.440 0.000 356.840 0.400 ;
    END
  END Tile_X1Y0_S4BEG[11]
  PIN Tile_X1Y0_S4BEG[12]
    DIRECTION OUTPUT ;
    USE SIGNAL ;
    ANTENNADIFFAREA 2.724000 ;
    PORT
      LAYER Metal2 ;
        RECT 357.400 0.000 357.800 0.400 ;
    END
  END Tile_X1Y0_S4BEG[12]
  PIN Tile_X1Y0_S4BEG[13]
    DIRECTION OUTPUT ;
    USE SIGNAL ;
    ANTENNADIFFAREA 2.724000 ;
    PORT
      LAYER Metal2 ;
        RECT 358.360 0.000 358.760 0.400 ;
    END
  END Tile_X1Y0_S4BEG[13]
  PIN Tile_X1Y0_S4BEG[14]
    DIRECTION OUTPUT ;
    USE SIGNAL ;
    ANTENNADIFFAREA 2.724000 ;
    PORT
      LAYER Metal2 ;
        RECT 359.320 0.000 359.720 0.400 ;
    END
  END Tile_X1Y0_S4BEG[14]
  PIN Tile_X1Y0_S4BEG[15]
    DIRECTION OUTPUT ;
    USE SIGNAL ;
    ANTENNADIFFAREA 2.724000 ;
    PORT
      LAYER Metal2 ;
        RECT 360.280 0.000 360.680 0.400 ;
    END
  END Tile_X1Y0_S4BEG[15]
  PIN Tile_X1Y0_S4BEG[1]
    DIRECTION OUTPUT ;
    USE SIGNAL ;
    ANTENNADIFFAREA 2.724000 ;
    PORT
      LAYER Metal2 ;
        RECT 346.840 0.000 347.240 0.400 ;
    END
  END Tile_X1Y0_S4BEG[1]
  PIN Tile_X1Y0_S4BEG[2]
    DIRECTION OUTPUT ;
    USE SIGNAL ;
    ANTENNADIFFAREA 2.724000 ;
    PORT
      LAYER Metal2 ;
        RECT 347.800 0.000 348.200 0.400 ;
    END
  END Tile_X1Y0_S4BEG[2]
  PIN Tile_X1Y0_S4BEG[3]
    DIRECTION OUTPUT ;
    USE SIGNAL ;
    ANTENNADIFFAREA 2.724000 ;
    PORT
      LAYER Metal2 ;
        RECT 348.760 0.000 349.160 0.400 ;
    END
  END Tile_X1Y0_S4BEG[3]
  PIN Tile_X1Y0_S4BEG[4]
    DIRECTION OUTPUT ;
    USE SIGNAL ;
    ANTENNADIFFAREA 2.724000 ;
    PORT
      LAYER Metal2 ;
        RECT 349.720 0.000 350.120 0.400 ;
    END
  END Tile_X1Y0_S4BEG[4]
  PIN Tile_X1Y0_S4BEG[5]
    DIRECTION OUTPUT ;
    USE SIGNAL ;
    ANTENNADIFFAREA 2.724000 ;
    PORT
      LAYER Metal2 ;
        RECT 350.680 0.000 351.080 0.400 ;
    END
  END Tile_X1Y0_S4BEG[5]
  PIN Tile_X1Y0_S4BEG[6]
    DIRECTION OUTPUT ;
    USE SIGNAL ;
    ANTENNADIFFAREA 2.724000 ;
    PORT
      LAYER Metal2 ;
        RECT 351.640 0.000 352.040 0.400 ;
    END
  END Tile_X1Y0_S4BEG[6]
  PIN Tile_X1Y0_S4BEG[7]
    DIRECTION OUTPUT ;
    USE SIGNAL ;
    ANTENNADIFFAREA 2.724000 ;
    PORT
      LAYER Metal2 ;
        RECT 352.600 0.000 353.000 0.400 ;
    END
  END Tile_X1Y0_S4BEG[7]
  PIN Tile_X1Y0_S4BEG[8]
    DIRECTION OUTPUT ;
    USE SIGNAL ;
    ANTENNADIFFAREA 2.724000 ;
    PORT
      LAYER Metal2 ;
        RECT 353.560 0.000 353.960 0.400 ;
    END
  END Tile_X1Y0_S4BEG[8]
  PIN Tile_X1Y0_S4BEG[9]
    DIRECTION OUTPUT ;
    USE SIGNAL ;
    ANTENNADIFFAREA 2.724000 ;
    PORT
      LAYER Metal2 ;
        RECT 354.520 0.000 354.920 0.400 ;
    END
  END Tile_X1Y0_S4BEG[9]
  PIN Tile_X1Y0_SS4BEG[0]
    DIRECTION OUTPUT ;
    USE SIGNAL ;
    ANTENNADIFFAREA 2.724000 ;
    PORT
      LAYER Metal2 ;
        RECT 373.720 0.000 374.120 0.400 ;
    END
  END Tile_X1Y0_SS4BEG[0]
  PIN Tile_X1Y0_SS4BEG[10]
    DIRECTION OUTPUT ;
    USE SIGNAL ;
    ANTENNADIFFAREA 2.724000 ;
    PORT
      LAYER Metal2 ;
        RECT 383.320 0.000 383.720 0.400 ;
    END
  END Tile_X1Y0_SS4BEG[10]
  PIN Tile_X1Y0_SS4BEG[11]
    DIRECTION OUTPUT ;
    USE SIGNAL ;
    ANTENNADIFFAREA 2.724000 ;
    PORT
      LAYER Metal2 ;
        RECT 384.280 0.000 384.680 0.400 ;
    END
  END Tile_X1Y0_SS4BEG[11]
  PIN Tile_X1Y0_SS4BEG[12]
    DIRECTION OUTPUT ;
    USE SIGNAL ;
    ANTENNADIFFAREA 2.724000 ;
    PORT
      LAYER Metal2 ;
        RECT 385.240 0.000 385.640 0.400 ;
    END
  END Tile_X1Y0_SS4BEG[12]
  PIN Tile_X1Y0_SS4BEG[13]
    DIRECTION OUTPUT ;
    USE SIGNAL ;
    ANTENNADIFFAREA 2.724000 ;
    PORT
      LAYER Metal2 ;
        RECT 386.200 0.000 386.600 0.400 ;
    END
  END Tile_X1Y0_SS4BEG[13]
  PIN Tile_X1Y0_SS4BEG[14]
    DIRECTION OUTPUT ;
    USE SIGNAL ;
    ANTENNADIFFAREA 2.724000 ;
    PORT
      LAYER Metal2 ;
        RECT 387.160 0.000 387.560 0.400 ;
    END
  END Tile_X1Y0_SS4BEG[14]
  PIN Tile_X1Y0_SS4BEG[15]
    DIRECTION OUTPUT ;
    USE SIGNAL ;
    ANTENNADIFFAREA 2.724000 ;
    PORT
      LAYER Metal2 ;
        RECT 388.120 0.000 388.520 0.400 ;
    END
  END Tile_X1Y0_SS4BEG[15]
  PIN Tile_X1Y0_SS4BEG[1]
    DIRECTION OUTPUT ;
    USE SIGNAL ;
    ANTENNADIFFAREA 2.724000 ;
    PORT
      LAYER Metal2 ;
        RECT 374.680 0.000 375.080 0.400 ;
    END
  END Tile_X1Y0_SS4BEG[1]
  PIN Tile_X1Y0_SS4BEG[2]
    DIRECTION OUTPUT ;
    USE SIGNAL ;
    ANTENNADIFFAREA 2.724000 ;
    PORT
      LAYER Metal2 ;
        RECT 375.640 0.000 376.040 0.400 ;
    END
  END Tile_X1Y0_SS4BEG[2]
  PIN Tile_X1Y0_SS4BEG[3]
    DIRECTION OUTPUT ;
    USE SIGNAL ;
    ANTENNADIFFAREA 2.724000 ;
    PORT
      LAYER Metal2 ;
        RECT 376.600 0.000 377.000 0.400 ;
    END
  END Tile_X1Y0_SS4BEG[3]
  PIN Tile_X1Y0_SS4BEG[4]
    DIRECTION OUTPUT ;
    USE SIGNAL ;
    ANTENNADIFFAREA 2.724000 ;
    PORT
      LAYER Metal2 ;
        RECT 377.560 0.000 377.960 0.400 ;
    END
  END Tile_X1Y0_SS4BEG[4]
  PIN Tile_X1Y0_SS4BEG[5]
    DIRECTION OUTPUT ;
    USE SIGNAL ;
    ANTENNADIFFAREA 2.724000 ;
    PORT
      LAYER Metal2 ;
        RECT 378.520 0.000 378.920 0.400 ;
    END
  END Tile_X1Y0_SS4BEG[5]
  PIN Tile_X1Y0_SS4BEG[6]
    DIRECTION OUTPUT ;
    USE SIGNAL ;
    ANTENNADIFFAREA 2.724000 ;
    PORT
      LAYER Metal2 ;
        RECT 379.480 0.000 379.880 0.400 ;
    END
  END Tile_X1Y0_SS4BEG[6]
  PIN Tile_X1Y0_SS4BEG[7]
    DIRECTION OUTPUT ;
    USE SIGNAL ;
    ANTENNADIFFAREA 2.724000 ;
    PORT
      LAYER Metal2 ;
        RECT 380.440 0.000 380.840 0.400 ;
    END
  END Tile_X1Y0_SS4BEG[7]
  PIN Tile_X1Y0_SS4BEG[8]
    DIRECTION OUTPUT ;
    USE SIGNAL ;
    ANTENNADIFFAREA 2.724000 ;
    PORT
      LAYER Metal2 ;
        RECT 381.400 0.000 381.800 0.400 ;
    END
  END Tile_X1Y0_SS4BEG[8]
  PIN Tile_X1Y0_SS4BEG[9]
    DIRECTION OUTPUT ;
    USE SIGNAL ;
    ANTENNADIFFAREA 2.724000 ;
    PORT
      LAYER Metal2 ;
        RECT 382.360 0.000 382.760 0.400 ;
    END
  END Tile_X1Y0_SS4BEG[9]
  PIN Tile_X1Y0_UserCLKo
    DIRECTION OUTPUT ;
    USE SIGNAL ;
    ANTENNADIFFAREA 2.724000 ;
    PORT
      LAYER Metal3 ;
        RECT 431.600 1.060 432.000 1.460 ;
    END
  END Tile_X1Y0_UserCLKo
  PIN VGND
    DIRECTION INOUT ;
    USE GROUND ;
    PORT
      LAYER Metal4 ;
        RECT 21.580 0.000 23.780 54.600 ;
    END
    PORT
      LAYER Metal4 ;
        RECT 97.180 0.000 99.380 54.600 ;
    END
    PORT
      LAYER Metal4 ;
        RECT 172.780 0.000 174.980 54.600 ;
    END
    PORT
      LAYER Metal4 ;
        RECT 248.380 0.000 250.580 54.600 ;
    END
    PORT
      LAYER Metal4 ;
        RECT 323.980 0.000 326.180 54.600 ;
    END
    PORT
      LAYER Metal4 ;
        RECT 399.580 0.000 401.780 54.600 ;
    END
  END VGND
  PIN VPWR
    DIRECTION INOUT ;
    USE POWER ;
    PORT
      LAYER Metal4 ;
        RECT 15.380 0.000 17.580 54.600 ;
    END
    PORT
      LAYER Metal4 ;
        RECT 90.980 0.000 93.180 54.600 ;
    END
    PORT
      LAYER Metal4 ;
        RECT 166.580 0.000 168.780 54.600 ;
    END
    PORT
      LAYER Metal4 ;
        RECT 242.180 0.000 244.380 54.600 ;
    END
    PORT
      LAYER Metal4 ;
        RECT 317.780 0.000 319.980 54.600 ;
    END
    PORT
      LAYER Metal4 ;
        RECT 393.380 0.000 395.580 54.600 ;
    END
  END VPWR
  OBS
      LAYER GatPoly ;
        RECT 2.880 3.630 429.120 49.290 ;
      LAYER Metal1 ;
        RECT 2.880 3.560 429.120 49.360 ;
      LAYER Metal2 ;
        RECT 2.295 53.990 7.750 54.325 ;
        RECT 8.570 53.990 18.310 54.325 ;
        RECT 19.130 53.990 28.870 54.325 ;
        RECT 29.690 53.990 39.430 54.325 ;
        RECT 40.250 53.990 49.990 54.325 ;
        RECT 50.810 53.990 60.550 54.325 ;
        RECT 61.370 53.990 71.110 54.325 ;
        RECT 71.930 53.990 81.670 54.325 ;
        RECT 82.490 53.990 92.230 54.325 ;
        RECT 93.050 53.990 102.790 54.325 ;
        RECT 103.610 53.990 113.350 54.325 ;
        RECT 114.170 53.990 123.910 54.325 ;
        RECT 124.730 53.990 134.470 54.325 ;
        RECT 135.290 53.990 145.030 54.325 ;
        RECT 145.850 53.990 155.590 54.325 ;
        RECT 156.410 53.990 166.150 54.325 ;
        RECT 166.970 53.990 176.710 54.325 ;
        RECT 177.530 53.990 187.270 54.325 ;
        RECT 188.090 53.990 197.830 54.325 ;
        RECT 198.650 53.990 208.390 54.325 ;
        RECT 209.210 53.990 218.950 54.325 ;
        RECT 219.770 53.990 220.870 54.325 ;
        RECT 221.690 53.990 222.790 54.325 ;
        RECT 223.610 53.990 224.710 54.325 ;
        RECT 225.530 53.990 226.630 54.325 ;
        RECT 227.450 53.990 228.550 54.325 ;
        RECT 229.370 53.990 230.470 54.325 ;
        RECT 231.290 53.990 232.390 54.325 ;
        RECT 233.210 53.990 234.310 54.325 ;
        RECT 235.130 53.990 236.230 54.325 ;
        RECT 237.050 53.990 238.150 54.325 ;
        RECT 238.970 53.990 240.070 54.325 ;
        RECT 240.890 53.990 241.990 54.325 ;
        RECT 242.810 53.990 243.910 54.325 ;
        RECT 244.730 53.990 245.830 54.325 ;
        RECT 246.650 53.990 247.750 54.325 ;
        RECT 248.570 53.990 249.670 54.325 ;
        RECT 250.490 53.990 251.590 54.325 ;
        RECT 252.410 53.990 253.510 54.325 ;
        RECT 254.330 53.990 255.430 54.325 ;
        RECT 256.250 53.990 265.990 54.325 ;
        RECT 266.810 53.990 267.910 54.325 ;
        RECT 268.730 53.990 269.830 54.325 ;
        RECT 270.650 53.990 271.750 54.325 ;
        RECT 272.570 53.990 273.670 54.325 ;
        RECT 274.490 53.990 275.590 54.325 ;
        RECT 276.410 53.990 277.510 54.325 ;
        RECT 278.330 53.990 279.430 54.325 ;
        RECT 280.250 53.990 281.350 54.325 ;
        RECT 282.170 53.990 283.270 54.325 ;
        RECT 284.090 53.990 285.190 54.325 ;
        RECT 286.010 53.990 287.110 54.325 ;
        RECT 287.930 53.990 289.030 54.325 ;
        RECT 289.850 53.990 290.950 54.325 ;
        RECT 291.770 53.990 292.870 54.325 ;
        RECT 293.690 53.990 294.790 54.325 ;
        RECT 295.610 53.990 296.710 54.325 ;
        RECT 297.530 53.990 298.630 54.325 ;
        RECT 299.450 53.990 300.550 54.325 ;
        RECT 301.370 53.990 302.470 54.325 ;
        RECT 303.290 53.990 304.390 54.325 ;
        RECT 305.210 53.990 306.310 54.325 ;
        RECT 307.130 53.990 308.230 54.325 ;
        RECT 309.050 53.990 310.150 54.325 ;
        RECT 310.970 53.990 312.070 54.325 ;
        RECT 312.890 53.990 313.990 54.325 ;
        RECT 314.810 53.990 315.910 54.325 ;
        RECT 316.730 53.990 317.830 54.325 ;
        RECT 318.650 53.990 319.750 54.325 ;
        RECT 320.570 53.990 321.670 54.325 ;
        RECT 322.490 53.990 323.590 54.325 ;
        RECT 324.410 53.990 325.510 54.325 ;
        RECT 326.330 53.990 327.430 54.325 ;
        RECT 328.250 53.990 329.350 54.325 ;
        RECT 330.170 53.990 331.270 54.325 ;
        RECT 332.090 53.990 333.190 54.325 ;
        RECT 334.010 53.990 335.110 54.325 ;
        RECT 335.930 53.990 337.030 54.325 ;
        RECT 337.850 53.990 338.950 54.325 ;
        RECT 339.770 53.990 340.870 54.325 ;
        RECT 341.690 53.990 342.790 54.325 ;
        RECT 343.610 53.990 344.710 54.325 ;
        RECT 345.530 53.990 346.630 54.325 ;
        RECT 347.450 53.990 348.550 54.325 ;
        RECT 349.370 53.990 350.470 54.325 ;
        RECT 351.290 53.990 352.390 54.325 ;
        RECT 353.210 53.990 354.310 54.325 ;
        RECT 355.130 53.990 356.230 54.325 ;
        RECT 357.050 53.990 358.150 54.325 ;
        RECT 358.970 53.990 360.070 54.325 ;
        RECT 360.890 53.990 361.990 54.325 ;
        RECT 362.810 53.990 363.910 54.325 ;
        RECT 364.730 53.990 365.830 54.325 ;
        RECT 366.650 53.990 367.750 54.325 ;
        RECT 368.570 53.990 369.670 54.325 ;
        RECT 370.490 53.990 371.590 54.325 ;
        RECT 372.410 53.990 373.510 54.325 ;
        RECT 374.330 53.990 375.430 54.325 ;
        RECT 376.250 53.990 377.350 54.325 ;
        RECT 378.170 53.990 379.270 54.325 ;
        RECT 380.090 53.990 381.190 54.325 ;
        RECT 382.010 53.990 383.110 54.325 ;
        RECT 383.930 53.990 385.030 54.325 ;
        RECT 385.850 53.990 386.950 54.325 ;
        RECT 387.770 53.990 388.870 54.325 ;
        RECT 389.690 53.990 390.790 54.325 ;
        RECT 391.610 53.990 392.710 54.325 ;
        RECT 393.530 53.990 394.630 54.325 ;
        RECT 395.450 53.990 396.550 54.325 ;
        RECT 397.370 53.990 398.470 54.325 ;
        RECT 399.290 53.990 400.390 54.325 ;
        RECT 401.210 53.990 402.310 54.325 ;
        RECT 403.130 53.990 404.230 54.325 ;
        RECT 405.050 53.990 406.150 54.325 ;
        RECT 406.970 53.990 408.070 54.325 ;
        RECT 408.890 53.990 409.990 54.325 ;
        RECT 410.810 53.990 411.910 54.325 ;
        RECT 412.730 53.990 413.830 54.325 ;
        RECT 414.650 53.990 415.750 54.325 ;
        RECT 416.570 53.990 417.670 54.325 ;
        RECT 418.490 53.990 419.590 54.325 ;
        RECT 420.410 53.990 421.510 54.325 ;
        RECT 422.330 53.990 423.430 54.325 ;
        RECT 424.250 53.990 425.865 54.325 ;
        RECT 2.295 0.610 425.865 53.990 ;
        RECT 2.810 0.275 2.950 0.610 ;
        RECT 3.770 0.275 3.910 0.610 ;
        RECT 4.730 0.275 4.870 0.610 ;
        RECT 5.690 0.275 10.630 0.610 ;
        RECT 11.450 0.275 11.590 0.610 ;
        RECT 12.410 0.275 12.550 0.610 ;
        RECT 13.370 0.275 13.510 0.610 ;
        RECT 14.330 0.275 14.470 0.610 ;
        RECT 15.290 0.275 15.430 0.610 ;
        RECT 16.250 0.275 16.390 0.610 ;
        RECT 17.210 0.275 17.350 0.610 ;
        RECT 18.170 0.275 24.070 0.610 ;
        RECT 24.890 0.275 25.030 0.610 ;
        RECT 25.850 0.275 25.990 0.610 ;
        RECT 26.810 0.275 26.950 0.610 ;
        RECT 27.770 0.275 27.910 0.610 ;
        RECT 28.730 0.275 28.870 0.610 ;
        RECT 29.690 0.275 29.830 0.610 ;
        RECT 30.650 0.275 30.790 0.610 ;
        RECT 31.610 0.275 40.390 0.610 ;
        RECT 41.210 0.275 41.350 0.610 ;
        RECT 42.170 0.275 42.310 0.610 ;
        RECT 43.130 0.275 43.270 0.610 ;
        RECT 44.090 0.275 44.230 0.610 ;
        RECT 45.050 0.275 45.190 0.610 ;
        RECT 46.010 0.275 46.150 0.610 ;
        RECT 46.970 0.275 47.110 0.610 ;
        RECT 47.930 0.275 48.070 0.610 ;
        RECT 48.890 0.275 49.030 0.610 ;
        RECT 49.850 0.275 49.990 0.610 ;
        RECT 50.810 0.275 50.950 0.610 ;
        RECT 51.770 0.275 51.910 0.610 ;
        RECT 52.730 0.275 52.870 0.610 ;
        RECT 53.690 0.275 53.830 0.610 ;
        RECT 54.650 0.275 54.790 0.610 ;
        RECT 55.610 0.275 68.230 0.610 ;
        RECT 69.050 0.275 69.190 0.610 ;
        RECT 70.010 0.275 70.150 0.610 ;
        RECT 70.970 0.275 71.110 0.610 ;
        RECT 71.930 0.275 72.070 0.610 ;
        RECT 72.890 0.275 73.030 0.610 ;
        RECT 73.850 0.275 73.990 0.610 ;
        RECT 74.810 0.275 74.950 0.610 ;
        RECT 75.770 0.275 75.910 0.610 ;
        RECT 76.730 0.275 76.870 0.610 ;
        RECT 77.690 0.275 77.830 0.610 ;
        RECT 78.650 0.275 78.790 0.610 ;
        RECT 79.610 0.275 79.750 0.610 ;
        RECT 80.570 0.275 80.710 0.610 ;
        RECT 81.530 0.275 81.670 0.610 ;
        RECT 82.490 0.275 82.630 0.610 ;
        RECT 83.450 0.275 90.310 0.610 ;
        RECT 91.130 0.275 91.270 0.610 ;
        RECT 92.090 0.275 92.230 0.610 ;
        RECT 93.050 0.275 93.190 0.610 ;
        RECT 94.010 0.275 98.950 0.610 ;
        RECT 99.770 0.275 99.910 0.610 ;
        RECT 100.730 0.275 100.870 0.610 ;
        RECT 101.690 0.275 101.830 0.610 ;
        RECT 102.650 0.275 102.790 0.610 ;
        RECT 103.610 0.275 103.750 0.610 ;
        RECT 104.570 0.275 104.710 0.610 ;
        RECT 105.530 0.275 105.670 0.610 ;
        RECT 106.490 0.275 113.350 0.610 ;
        RECT 114.170 0.275 114.310 0.610 ;
        RECT 115.130 0.275 115.270 0.610 ;
        RECT 116.090 0.275 116.230 0.610 ;
        RECT 117.050 0.275 117.190 0.610 ;
        RECT 118.010 0.275 118.150 0.610 ;
        RECT 118.970 0.275 119.110 0.610 ;
        RECT 119.930 0.275 120.070 0.610 ;
        RECT 120.890 0.275 129.670 0.610 ;
        RECT 130.490 0.275 130.630 0.610 ;
        RECT 131.450 0.275 131.590 0.610 ;
        RECT 132.410 0.275 132.550 0.610 ;
        RECT 133.370 0.275 133.510 0.610 ;
        RECT 134.330 0.275 134.470 0.610 ;
        RECT 135.290 0.275 135.430 0.610 ;
        RECT 136.250 0.275 136.390 0.610 ;
        RECT 137.210 0.275 137.350 0.610 ;
        RECT 138.170 0.275 138.310 0.610 ;
        RECT 139.130 0.275 139.270 0.610 ;
        RECT 140.090 0.275 140.230 0.610 ;
        RECT 141.050 0.275 141.190 0.610 ;
        RECT 142.010 0.275 142.150 0.610 ;
        RECT 142.970 0.275 143.110 0.610 ;
        RECT 143.930 0.275 144.070 0.610 ;
        RECT 144.890 0.275 157.510 0.610 ;
        RECT 158.330 0.275 158.470 0.610 ;
        RECT 159.290 0.275 159.430 0.610 ;
        RECT 160.250 0.275 160.390 0.610 ;
        RECT 161.210 0.275 161.350 0.610 ;
        RECT 162.170 0.275 162.310 0.610 ;
        RECT 163.130 0.275 163.270 0.610 ;
        RECT 164.090 0.275 164.230 0.610 ;
        RECT 165.050 0.275 165.190 0.610 ;
        RECT 166.010 0.275 166.150 0.610 ;
        RECT 166.970 0.275 167.110 0.610 ;
        RECT 167.930 0.275 168.070 0.610 ;
        RECT 168.890 0.275 169.030 0.610 ;
        RECT 169.850 0.275 169.990 0.610 ;
        RECT 170.810 0.275 170.950 0.610 ;
        RECT 171.770 0.275 171.910 0.610 ;
        RECT 172.730 0.275 179.590 0.610 ;
        RECT 180.410 0.275 189.190 0.610 ;
        RECT 190.010 0.275 190.150 0.610 ;
        RECT 190.970 0.275 191.110 0.610 ;
        RECT 191.930 0.275 192.070 0.610 ;
        RECT 192.890 0.275 193.030 0.610 ;
        RECT 193.850 0.275 193.990 0.610 ;
        RECT 194.810 0.275 194.950 0.610 ;
        RECT 195.770 0.275 195.910 0.610 ;
        RECT 196.730 0.275 196.870 0.610 ;
        RECT 197.690 0.275 197.830 0.610 ;
        RECT 198.650 0.275 198.790 0.610 ;
        RECT 199.610 0.275 199.750 0.610 ;
        RECT 200.570 0.275 200.710 0.610 ;
        RECT 201.530 0.275 201.670 0.610 ;
        RECT 202.490 0.275 202.630 0.610 ;
        RECT 203.450 0.275 203.590 0.610 ;
        RECT 204.410 0.275 204.550 0.610 ;
        RECT 205.370 0.275 205.510 0.610 ;
        RECT 206.330 0.275 206.470 0.610 ;
        RECT 207.290 0.275 207.430 0.610 ;
        RECT 208.250 0.275 217.990 0.610 ;
        RECT 218.810 0.275 218.950 0.610 ;
        RECT 219.770 0.275 219.910 0.610 ;
        RECT 220.730 0.275 220.870 0.610 ;
        RECT 221.690 0.275 226.630 0.610 ;
        RECT 227.450 0.275 227.590 0.610 ;
        RECT 228.410 0.275 228.550 0.610 ;
        RECT 229.370 0.275 229.510 0.610 ;
        RECT 230.330 0.275 230.470 0.610 ;
        RECT 231.290 0.275 231.430 0.610 ;
        RECT 232.250 0.275 232.390 0.610 ;
        RECT 233.210 0.275 233.350 0.610 ;
        RECT 234.170 0.275 240.070 0.610 ;
        RECT 240.890 0.275 241.030 0.610 ;
        RECT 241.850 0.275 241.990 0.610 ;
        RECT 242.810 0.275 242.950 0.610 ;
        RECT 243.770 0.275 243.910 0.610 ;
        RECT 244.730 0.275 244.870 0.610 ;
        RECT 245.690 0.275 245.830 0.610 ;
        RECT 246.650 0.275 246.790 0.610 ;
        RECT 247.610 0.275 256.390 0.610 ;
        RECT 257.210 0.275 257.350 0.610 ;
        RECT 258.170 0.275 258.310 0.610 ;
        RECT 259.130 0.275 259.270 0.610 ;
        RECT 260.090 0.275 260.230 0.610 ;
        RECT 261.050 0.275 261.190 0.610 ;
        RECT 262.010 0.275 262.150 0.610 ;
        RECT 262.970 0.275 263.110 0.610 ;
        RECT 263.930 0.275 264.070 0.610 ;
        RECT 264.890 0.275 265.030 0.610 ;
        RECT 265.850 0.275 265.990 0.610 ;
        RECT 266.810 0.275 266.950 0.610 ;
        RECT 267.770 0.275 267.910 0.610 ;
        RECT 268.730 0.275 268.870 0.610 ;
        RECT 269.690 0.275 269.830 0.610 ;
        RECT 270.650 0.275 270.790 0.610 ;
        RECT 271.610 0.275 284.230 0.610 ;
        RECT 285.050 0.275 285.190 0.610 ;
        RECT 286.010 0.275 286.150 0.610 ;
        RECT 286.970 0.275 287.110 0.610 ;
        RECT 287.930 0.275 288.070 0.610 ;
        RECT 288.890 0.275 289.030 0.610 ;
        RECT 289.850 0.275 289.990 0.610 ;
        RECT 290.810 0.275 290.950 0.610 ;
        RECT 291.770 0.275 291.910 0.610 ;
        RECT 292.730 0.275 292.870 0.610 ;
        RECT 293.690 0.275 293.830 0.610 ;
        RECT 294.650 0.275 294.790 0.610 ;
        RECT 295.610 0.275 295.750 0.610 ;
        RECT 296.570 0.275 296.710 0.610 ;
        RECT 297.530 0.275 297.670 0.610 ;
        RECT 298.490 0.275 298.630 0.610 ;
        RECT 299.450 0.275 306.310 0.610 ;
        RECT 307.130 0.275 307.270 0.610 ;
        RECT 308.090 0.275 308.230 0.610 ;
        RECT 309.050 0.275 309.190 0.610 ;
        RECT 310.010 0.275 314.950 0.610 ;
        RECT 315.770 0.275 315.910 0.610 ;
        RECT 316.730 0.275 316.870 0.610 ;
        RECT 317.690 0.275 317.830 0.610 ;
        RECT 318.650 0.275 318.790 0.610 ;
        RECT 319.610 0.275 319.750 0.610 ;
        RECT 320.570 0.275 320.710 0.610 ;
        RECT 321.530 0.275 321.670 0.610 ;
        RECT 322.490 0.275 329.350 0.610 ;
        RECT 330.170 0.275 330.310 0.610 ;
        RECT 331.130 0.275 331.270 0.610 ;
        RECT 332.090 0.275 332.230 0.610 ;
        RECT 333.050 0.275 333.190 0.610 ;
        RECT 334.010 0.275 334.150 0.610 ;
        RECT 334.970 0.275 335.110 0.610 ;
        RECT 335.930 0.275 336.070 0.610 ;
        RECT 336.890 0.275 345.670 0.610 ;
        RECT 346.490 0.275 346.630 0.610 ;
        RECT 347.450 0.275 347.590 0.610 ;
        RECT 348.410 0.275 348.550 0.610 ;
        RECT 349.370 0.275 349.510 0.610 ;
        RECT 350.330 0.275 350.470 0.610 ;
        RECT 351.290 0.275 351.430 0.610 ;
        RECT 352.250 0.275 352.390 0.610 ;
        RECT 353.210 0.275 353.350 0.610 ;
        RECT 354.170 0.275 354.310 0.610 ;
        RECT 355.130 0.275 355.270 0.610 ;
        RECT 356.090 0.275 356.230 0.610 ;
        RECT 357.050 0.275 357.190 0.610 ;
        RECT 358.010 0.275 358.150 0.610 ;
        RECT 358.970 0.275 359.110 0.610 ;
        RECT 359.930 0.275 360.070 0.610 ;
        RECT 360.890 0.275 373.510 0.610 ;
        RECT 374.330 0.275 374.470 0.610 ;
        RECT 375.290 0.275 375.430 0.610 ;
        RECT 376.250 0.275 376.390 0.610 ;
        RECT 377.210 0.275 377.350 0.610 ;
        RECT 378.170 0.275 378.310 0.610 ;
        RECT 379.130 0.275 379.270 0.610 ;
        RECT 380.090 0.275 380.230 0.610 ;
        RECT 381.050 0.275 381.190 0.610 ;
        RECT 382.010 0.275 382.150 0.610 ;
        RECT 382.970 0.275 383.110 0.610 ;
        RECT 383.930 0.275 384.070 0.610 ;
        RECT 384.890 0.275 385.030 0.610 ;
        RECT 385.850 0.275 385.990 0.610 ;
        RECT 386.810 0.275 386.950 0.610 ;
        RECT 387.770 0.275 387.910 0.610 ;
        RECT 388.730 0.275 395.590 0.610 ;
        RECT 396.410 0.275 405.190 0.610 ;
        RECT 406.010 0.275 406.150 0.610 ;
        RECT 406.970 0.275 407.110 0.610 ;
        RECT 407.930 0.275 408.070 0.610 ;
        RECT 408.890 0.275 409.030 0.610 ;
        RECT 409.850 0.275 409.990 0.610 ;
        RECT 410.810 0.275 410.950 0.610 ;
        RECT 411.770 0.275 411.910 0.610 ;
        RECT 412.730 0.275 412.870 0.610 ;
        RECT 413.690 0.275 413.830 0.610 ;
        RECT 414.650 0.275 414.790 0.610 ;
        RECT 415.610 0.275 415.750 0.610 ;
        RECT 416.570 0.275 416.710 0.610 ;
        RECT 417.530 0.275 417.670 0.610 ;
        RECT 418.490 0.275 418.630 0.610 ;
        RECT 419.450 0.275 419.590 0.610 ;
        RECT 420.410 0.275 420.550 0.610 ;
        RECT 421.370 0.275 421.510 0.610 ;
        RECT 422.330 0.275 422.470 0.610 ;
        RECT 423.290 0.275 423.430 0.610 ;
        RECT 424.250 0.275 425.865 0.610 ;
      LAYER Metal3 ;
        RECT 0.400 41.990 431.600 54.285 ;
        RECT 0.610 41.170 431.390 41.990 ;
        RECT 0.400 41.150 431.600 41.170 ;
        RECT 0.610 40.330 431.390 41.150 ;
        RECT 0.400 40.310 431.600 40.330 ;
        RECT 0.610 39.490 431.390 40.310 ;
        RECT 0.400 39.470 431.600 39.490 ;
        RECT 0.610 38.650 431.390 39.470 ;
        RECT 0.400 38.630 431.600 38.650 ;
        RECT 0.610 37.810 431.390 38.630 ;
        RECT 0.400 37.790 431.600 37.810 ;
        RECT 0.610 36.970 431.390 37.790 ;
        RECT 0.400 36.950 431.600 36.970 ;
        RECT 0.610 36.130 431.390 36.950 ;
        RECT 0.400 36.110 431.600 36.130 ;
        RECT 0.610 35.290 431.390 36.110 ;
        RECT 0.400 35.270 431.600 35.290 ;
        RECT 0.610 34.450 431.390 35.270 ;
        RECT 0.400 34.430 431.600 34.450 ;
        RECT 0.610 33.610 431.390 34.430 ;
        RECT 0.400 33.590 431.600 33.610 ;
        RECT 0.610 32.770 431.390 33.590 ;
        RECT 0.400 32.750 431.600 32.770 ;
        RECT 0.610 31.930 431.390 32.750 ;
        RECT 0.400 31.910 431.600 31.930 ;
        RECT 0.610 31.090 431.390 31.910 ;
        RECT 0.400 31.070 431.600 31.090 ;
        RECT 0.610 30.250 431.390 31.070 ;
        RECT 0.400 30.230 431.600 30.250 ;
        RECT 0.610 29.410 431.390 30.230 ;
        RECT 0.400 29.390 431.600 29.410 ;
        RECT 0.610 28.570 431.390 29.390 ;
        RECT 0.400 28.550 431.600 28.570 ;
        RECT 0.610 27.730 431.390 28.550 ;
        RECT 0.400 27.710 431.600 27.730 ;
        RECT 0.610 26.890 431.390 27.710 ;
        RECT 0.400 26.870 431.600 26.890 ;
        RECT 0.610 26.050 431.390 26.870 ;
        RECT 0.400 26.030 431.600 26.050 ;
        RECT 0.610 25.210 431.390 26.030 ;
        RECT 0.400 25.190 431.600 25.210 ;
        RECT 0.610 24.370 431.390 25.190 ;
        RECT 0.400 24.350 431.600 24.370 ;
        RECT 0.610 23.530 431.390 24.350 ;
        RECT 0.400 23.510 431.600 23.530 ;
        RECT 0.610 22.690 431.390 23.510 ;
        RECT 0.400 22.670 431.600 22.690 ;
        RECT 0.610 21.850 431.390 22.670 ;
        RECT 0.400 21.830 431.600 21.850 ;
        RECT 0.610 21.010 431.390 21.830 ;
        RECT 0.400 20.990 431.600 21.010 ;
        RECT 0.610 20.170 431.390 20.990 ;
        RECT 0.400 20.150 431.600 20.170 ;
        RECT 0.610 19.330 431.390 20.150 ;
        RECT 0.400 19.310 431.600 19.330 ;
        RECT 0.610 18.490 431.390 19.310 ;
        RECT 0.400 18.470 431.600 18.490 ;
        RECT 0.610 17.650 431.390 18.470 ;
        RECT 0.400 17.630 431.600 17.650 ;
        RECT 0.610 16.810 431.390 17.630 ;
        RECT 0.400 16.790 431.600 16.810 ;
        RECT 0.610 15.970 431.390 16.790 ;
        RECT 0.400 15.950 431.600 15.970 ;
        RECT 0.610 15.130 431.390 15.950 ;
        RECT 0.400 1.670 431.600 15.130 ;
        RECT 0.610 0.850 431.390 1.670 ;
        RECT 0.400 0.315 431.600 0.850 ;
      LAYER Metal4 ;
        RECT 4.490 0.275 15.170 54.325 ;
        RECT 17.790 0.275 21.370 54.325 ;
        RECT 23.990 0.275 90.770 54.325 ;
        RECT 93.390 0.275 96.970 54.325 ;
        RECT 99.590 0.275 166.370 54.325 ;
        RECT 168.990 0.275 172.570 54.325 ;
        RECT 175.190 0.275 241.970 54.325 ;
        RECT 244.590 0.275 248.170 54.325 ;
        RECT 250.790 0.275 317.570 54.325 ;
        RECT 320.190 0.275 323.770 54.325 ;
        RECT 326.390 0.275 393.170 54.325 ;
        RECT 395.790 0.275 399.370 54.325 ;
        RECT 401.990 0.275 428.470 54.325 ;
      LAYER TopMetal1 ;
        RECT 3.980 3.100 428.980 52.620 ;
  END
END NPU_PSUM_PORT
END LIBRARY

